VERSION 5.8 ;
BUSBITCHARS "[]" ;
DIVIDERCHAR "/" ;
UNITS
    DATABASE MICRONS 1000 ;
END UNITS

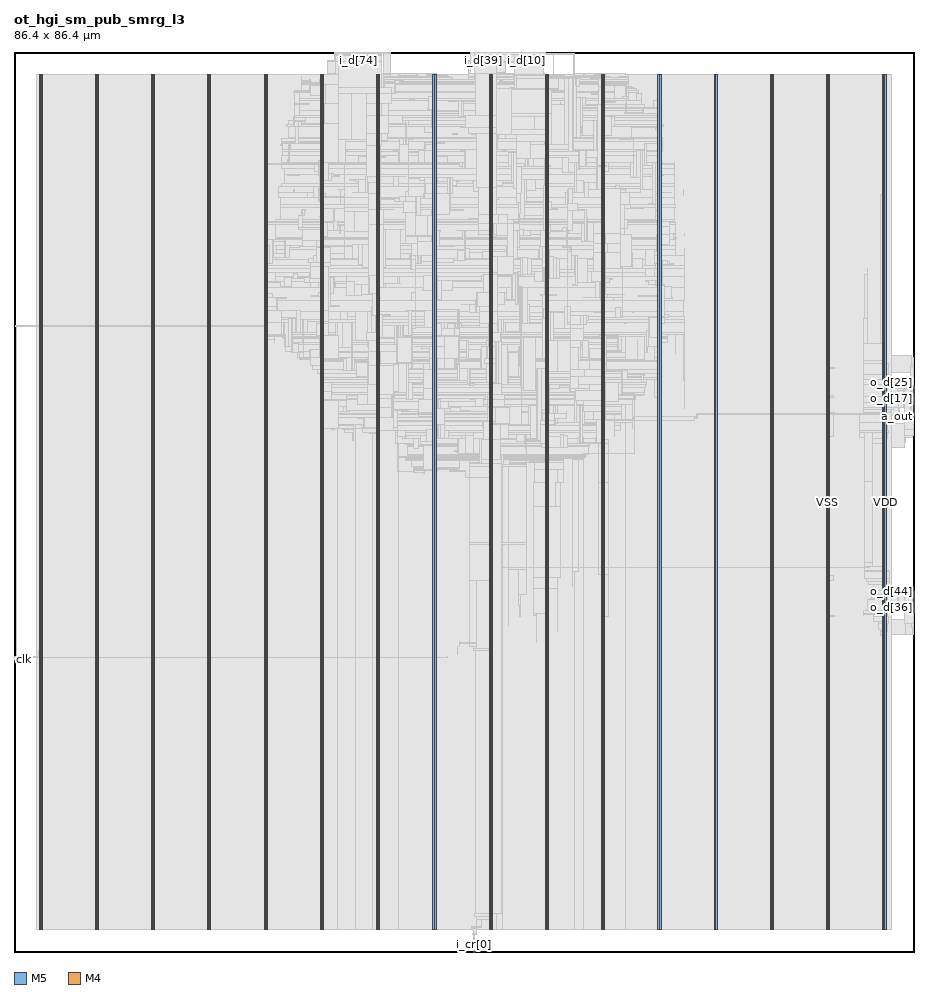
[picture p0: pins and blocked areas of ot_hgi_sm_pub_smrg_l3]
MACRO ot_hgi_sm_pub_smrg_l3
  FOREIGN ot_hgi_sm_pub_smrg_l3 0 0 ;
  CLASS BLOCK ;
  SIZE 86.4 BY 86.4 ;
  PIN a_in[0]
    DIRECTION INPUT ;
    USE SIGNAL ;
    PORT
      LAYER M5 ;
        RECT  48.048 86.316 48.072 86.4 ;
    END
  END a_in[0]
  PIN a_in[1]
    DIRECTION INPUT ;
    USE SIGNAL ;
    PORT
      LAYER M5 ;
        RECT  48.144 86.316 48.168 86.4 ;
    END
  END a_in[1]
  PIN a_out
    DIRECTION OUTPUT ;
    USE SIGNAL ;
    PORT
      LAYER M4 ;
        RECT  86.316 51.408 86.4 51.432 ;
    END
  END a_out
  PIN clk
    DIRECTION INPUT ;
    USE SIGNAL ;
    PORT
      LAYER M4 ;
        RECT  0 28.08 0.084 28.104 ;
    END
  END clk
  PIN i_cr[0]
    DIRECTION OUTPUT ;
    USE SIGNAL ;
    PORT
      LAYER M5 ;
        RECT  44.112 0 44.136 0.084 ;
    END
  END i_cr[0]
  PIN i_cr[1]
    DIRECTION OUTPUT ;
    USE SIGNAL ;
    PORT
      LAYER M5 ;
        RECT  44.208 0 44.232 0.084 ;
    END
  END i_cr[1]
  PIN i_d[0]
    DIRECTION INPUT ;
    USE SIGNAL ;
    PORT
      LAYER M5 ;
        RECT  48.24 86.316 48.264 86.4 ;
    END
  END i_d[0]
  PIN i_d[100]
    DIRECTION INPUT ;
    USE SIGNAL ;
    PORT
      LAYER M5 ;
        RECT  31.344 86.316 31.368 86.4 ;
    END
  END i_d[100]
  PIN i_d[101]
    DIRECTION INPUT ;
    USE SIGNAL ;
    PORT
      LAYER M5 ;
        RECT  31.44 86.316 31.464 86.4 ;
    END
  END i_d[101]
  PIN i_d[102]
    DIRECTION INPUT ;
    USE SIGNAL ;
    PORT
      LAYER M5 ;
        RECT  31.536 86.316 31.56 86.4 ;
    END
  END i_d[102]
  PIN i_d[103]
    DIRECTION INPUT ;
    USE SIGNAL ;
    PORT
      LAYER M5 ;
        RECT  31.632 86.316 31.656 86.4 ;
    END
  END i_d[103]
  PIN i_d[10]
    DIRECTION INPUT ;
    USE SIGNAL ;
    PORT
      LAYER M5 ;
        RECT  49.2 86.316 49.224 86.4 ;
    END
  END i_d[10]
  PIN i_d[11]
    DIRECTION INPUT ;
    USE SIGNAL ;
    PORT
      LAYER M5 ;
        RECT  49.296 86.316 49.32 86.4 ;
    END
  END i_d[11]
  PIN i_d[12]
    DIRECTION INPUT ;
    USE SIGNAL ;
    PORT
      LAYER M5 ;
        RECT  49.392 86.316 49.416 86.4 ;
    END
  END i_d[12]
  PIN i_d[13]
    DIRECTION INPUT ;
    USE SIGNAL ;
    PORT
      LAYER M5 ;
        RECT  49.488 86.316 49.512 86.4 ;
    END
  END i_d[13]
  PIN i_d[14]
    DIRECTION INPUT ;
    USE SIGNAL ;
    PORT
      LAYER M5 ;
        RECT  49.584 86.316 49.608 86.4 ;
    END
  END i_d[14]
  PIN i_d[15]
    DIRECTION INPUT ;
    USE SIGNAL ;
    PORT
      LAYER M5 ;
        RECT  49.68 86.316 49.704 86.4 ;
    END
  END i_d[15]
  PIN i_d[16]
    DIRECTION INPUT ;
    USE SIGNAL ;
    PORT
      LAYER M5 ;
        RECT  49.776 86.316 49.8 86.4 ;
    END
  END i_d[16]
  PIN i_d[17]
    DIRECTION INPUT ;
    USE SIGNAL ;
    PORT
      LAYER M5 ;
        RECT  49.872 86.316 49.896 86.4 ;
    END
  END i_d[17]
  PIN i_d[18]
    DIRECTION INPUT ;
    USE SIGNAL ;
    PORT
      LAYER M5 ;
        RECT  49.968 86.316 49.992 86.4 ;
    END
  END i_d[18]
  PIN i_d[19]
    DIRECTION INPUT ;
    USE SIGNAL ;
    PORT
      LAYER M5 ;
        RECT  50.064 86.316 50.088 86.4 ;
    END
  END i_d[19]
  PIN i_d[1]
    DIRECTION INPUT ;
    USE SIGNAL ;
    PORT
      LAYER M5 ;
        RECT  48.336 86.316 48.36 86.4 ;
    END
  END i_d[1]
  PIN i_d[20]
    DIRECTION INPUT ;
    USE SIGNAL ;
    PORT
      LAYER M5 ;
        RECT  50.16 86.316 50.184 86.4 ;
    END
  END i_d[20]
  PIN i_d[21]
    DIRECTION INPUT ;
    USE SIGNAL ;
    PORT
      LAYER M5 ;
        RECT  50.256 86.316 50.28 86.4 ;
    END
  END i_d[21]
  PIN i_d[22]
    DIRECTION INPUT ;
    USE SIGNAL ;
    PORT
      LAYER M5 ;
        RECT  50.352 86.316 50.376 86.4 ;
    END
  END i_d[22]
  PIN i_d[23]
    DIRECTION INPUT ;
    USE SIGNAL ;
    PORT
      LAYER M5 ;
        RECT  50.448 86.316 50.472 86.4 ;
    END
  END i_d[23]
  PIN i_d[24]
    DIRECTION INPUT ;
    USE SIGNAL ;
    PORT
      LAYER M5 ;
        RECT  50.544 86.316 50.568 86.4 ;
    END
  END i_d[24]
  PIN i_d[25]
    DIRECTION INPUT ;
    USE SIGNAL ;
    PORT
      LAYER M5 ;
        RECT  50.64 86.316 50.664 86.4 ;
    END
  END i_d[25]
  PIN i_d[26]
    DIRECTION INPUT ;
    USE SIGNAL ;
    PORT
      LAYER M5 ;
        RECT  50.736 86.316 50.76 86.4 ;
    END
  END i_d[26]
  PIN i_d[27]
    DIRECTION INPUT ;
    USE SIGNAL ;
    PORT
      LAYER M5 ;
        RECT  50.832 86.316 50.856 86.4 ;
    END
  END i_d[27]
  PIN i_d[28]
    DIRECTION INPUT ;
    USE SIGNAL ;
    PORT
      LAYER M5 ;
        RECT  50.928 86.316 50.952 86.4 ;
    END
  END i_d[28]
  PIN i_d[29]
    DIRECTION INPUT ;
    USE SIGNAL ;
    PORT
      LAYER M5 ;
        RECT  51.024 86.316 51.048 86.4 ;
    END
  END i_d[29]
  PIN i_d[2]
    DIRECTION INPUT ;
    USE SIGNAL ;
    PORT
      LAYER M5 ;
        RECT  48.432 86.316 48.456 86.4 ;
    END
  END i_d[2]
  PIN i_d[30]
    DIRECTION INPUT ;
    USE SIGNAL ;
    PORT
      LAYER M5 ;
        RECT  44.208 86.316 44.232 86.4 ;
    END
  END i_d[30]
  PIN i_d[31]
    DIRECTION INPUT ;
    USE SIGNAL ;
    PORT
      LAYER M5 ;
        RECT  44.304 86.316 44.328 86.4 ;
    END
  END i_d[31]
  PIN i_d[32]
    DIRECTION INPUT ;
    USE SIGNAL ;
    PORT
      LAYER M5 ;
        RECT  44.4 86.316 44.424 86.4 ;
    END
  END i_d[32]
  PIN i_d[33]
    DIRECTION INPUT ;
    USE SIGNAL ;
    PORT
      LAYER M5 ;
        RECT  44.496 86.316 44.52 86.4 ;
    END
  END i_d[33]
  PIN i_d[34]
    DIRECTION INPUT ;
    USE SIGNAL ;
    PORT
      LAYER M5 ;
        RECT  44.592 86.316 44.616 86.4 ;
    END
  END i_d[34]
  PIN i_d[35]
    DIRECTION INPUT ;
    USE SIGNAL ;
    PORT
      LAYER M5 ;
        RECT  44.688 86.316 44.712 86.4 ;
    END
  END i_d[35]
  PIN i_d[36]
    DIRECTION INPUT ;
    USE SIGNAL ;
    PORT
      LAYER M5 ;
        RECT  44.784 86.316 44.808 86.4 ;
    END
  END i_d[36]
  PIN i_d[37]
    DIRECTION INPUT ;
    USE SIGNAL ;
    PORT
      LAYER M5 ;
        RECT  44.88 86.316 44.904 86.4 ;
    END
  END i_d[37]
  PIN i_d[38]
    DIRECTION INPUT ;
    USE SIGNAL ;
    PORT
      LAYER M5 ;
        RECT  44.976 86.316 45 86.4 ;
    END
  END i_d[38]
  PIN i_d[39]
    DIRECTION INPUT ;
    USE SIGNAL ;
    PORT
      LAYER M5 ;
        RECT  45.072 86.316 45.096 86.4 ;
    END
  END i_d[39]
  PIN i_d[3]
    DIRECTION INPUT ;
    USE SIGNAL ;
    PORT
      LAYER M5 ;
        RECT  48.528 86.316 48.552 86.4 ;
    END
  END i_d[3]
  PIN i_d[40]
    DIRECTION INPUT ;
    USE SIGNAL ;
    PORT
      LAYER M5 ;
        RECT  45.168 86.316 45.192 86.4 ;
    END
  END i_d[40]
  PIN i_d[41]
    DIRECTION INPUT ;
    USE SIGNAL ;
    PORT
      LAYER M5 ;
        RECT  45.264 86.316 45.288 86.4 ;
    END
  END i_d[41]
  PIN i_d[42]
    DIRECTION INPUT ;
    USE SIGNAL ;
    PORT
      LAYER M5 ;
        RECT  45.36 86.316 45.384 86.4 ;
    END
  END i_d[42]
  PIN i_d[43]
    DIRECTION INPUT ;
    USE SIGNAL ;
    PORT
      LAYER M5 ;
        RECT  45.456 86.316 45.48 86.4 ;
    END
  END i_d[43]
  PIN i_d[44]
    DIRECTION INPUT ;
    USE SIGNAL ;
    PORT
      LAYER M5 ;
        RECT  45.552 86.316 45.576 86.4 ;
    END
  END i_d[44]
  PIN i_d[45]
    DIRECTION INPUT ;
    USE SIGNAL ;
    PORT
      LAYER M5 ;
        RECT  45.648 86.316 45.672 86.4 ;
    END
  END i_d[45]
  PIN i_d[46]
    DIRECTION INPUT ;
    USE SIGNAL ;
    PORT
      LAYER M5 ;
        RECT  45.744 86.316 45.768 86.4 ;
    END
  END i_d[46]
  PIN i_d[47]
    DIRECTION INPUT ;
    USE SIGNAL ;
    PORT
      LAYER M5 ;
        RECT  45.84 86.316 45.864 86.4 ;
    END
  END i_d[47]
  PIN i_d[48]
    DIRECTION INPUT ;
    USE SIGNAL ;
    PORT
      LAYER M5 ;
        RECT  45.936 86.316 45.96 86.4 ;
    END
  END i_d[48]
  PIN i_d[49]
    DIRECTION INPUT ;
    USE SIGNAL ;
    PORT
      LAYER M5 ;
        RECT  46.032 86.316 46.056 86.4 ;
    END
  END i_d[49]
  PIN i_d[4]
    DIRECTION INPUT ;
    USE SIGNAL ;
    PORT
      LAYER M5 ;
        RECT  48.624 86.316 48.648 86.4 ;
    END
  END i_d[4]
  PIN i_d[50]
    DIRECTION INPUT ;
    USE SIGNAL ;
    PORT
      LAYER M5 ;
        RECT  46.128 86.316 46.152 86.4 ;
    END
  END i_d[50]
  PIN i_d[51]
    DIRECTION INPUT ;
    USE SIGNAL ;
    PORT
      LAYER M5 ;
        RECT  46.224 86.316 46.248 86.4 ;
    END
  END i_d[51]
  PIN i_d[52]
    DIRECTION INPUT ;
    USE SIGNAL ;
    PORT
      LAYER M5 ;
        RECT  46.32 86.316 46.344 86.4 ;
    END
  END i_d[52]
  PIN i_d[53]
    DIRECTION INPUT ;
    USE SIGNAL ;
    PORT
      LAYER M5 ;
        RECT  46.416 86.316 46.44 86.4 ;
    END
  END i_d[53]
  PIN i_d[54]
    DIRECTION INPUT ;
    USE SIGNAL ;
    PORT
      LAYER M5 ;
        RECT  46.512 86.316 46.536 86.4 ;
    END
  END i_d[54]
  PIN i_d[55]
    DIRECTION INPUT ;
    USE SIGNAL ;
    PORT
      LAYER M5 ;
        RECT  46.608 86.316 46.632 86.4 ;
    END
  END i_d[55]
  PIN i_d[56]
    DIRECTION INPUT ;
    USE SIGNAL ;
    PORT
      LAYER M5 ;
        RECT  46.704 86.316 46.728 86.4 ;
    END
  END i_d[56]
  PIN i_d[57]
    DIRECTION INPUT ;
    USE SIGNAL ;
    PORT
      LAYER M5 ;
        RECT  46.8 86.316 46.824 86.4 ;
    END
  END i_d[57]
  PIN i_d[58]
    DIRECTION INPUT ;
    USE SIGNAL ;
    PORT
      LAYER M5 ;
        RECT  46.896 86.316 46.92 86.4 ;
    END
  END i_d[58]
  PIN i_d[59]
    DIRECTION INPUT ;
    USE SIGNAL ;
    PORT
      LAYER M5 ;
        RECT  46.992 86.316 47.016 86.4 ;
    END
  END i_d[59]
  PIN i_d[5]
    DIRECTION INPUT ;
    USE SIGNAL ;
    PORT
      LAYER M5 ;
        RECT  48.72 86.316 48.744 86.4 ;
    END
  END i_d[5]
  PIN i_d[60]
    DIRECTION INPUT ;
    USE SIGNAL ;
    PORT
      LAYER M5 ;
        RECT  47.088 86.316 47.112 86.4 ;
    END
  END i_d[60]
  PIN i_d[61]
    DIRECTION INPUT ;
    USE SIGNAL ;
    PORT
      LAYER M5 ;
        RECT  47.184 86.316 47.208 86.4 ;
    END
  END i_d[61]
  PIN i_d[62]
    DIRECTION INPUT ;
    USE SIGNAL ;
    PORT
      LAYER M5 ;
        RECT  31.92 86.316 31.944 86.4 ;
    END
  END i_d[62]
  PIN i_d[63]
    DIRECTION INPUT ;
    USE SIGNAL ;
    PORT
      LAYER M5 ;
        RECT  32.016 86.316 32.04 86.4 ;
    END
  END i_d[63]
  PIN i_d[64]
    DIRECTION INPUT ;
    USE SIGNAL ;
    PORT
      LAYER M5 ;
        RECT  32.112 86.316 32.136 86.4 ;
    END
  END i_d[64]
  PIN i_d[65]
    DIRECTION INPUT ;
    USE SIGNAL ;
    PORT
      LAYER M5 ;
        RECT  32.208 86.316 32.232 86.4 ;
    END
  END i_d[65]
  PIN i_d[66]
    DIRECTION INPUT ;
    USE SIGNAL ;
    PORT
      LAYER M5 ;
        RECT  32.304 86.316 32.328 86.4 ;
    END
  END i_d[66]
  PIN i_d[67]
    DIRECTION INPUT ;
    USE SIGNAL ;
    PORT
      LAYER M5 ;
        RECT  32.4 86.316 32.424 86.4 ;
    END
  END i_d[67]
  PIN i_d[68]
    DIRECTION INPUT ;
    USE SIGNAL ;
    PORT
      LAYER M5 ;
        RECT  32.496 86.316 32.52 86.4 ;
    END
  END i_d[68]
  PIN i_d[69]
    DIRECTION INPUT ;
    USE SIGNAL ;
    PORT
      LAYER M5 ;
        RECT  32.592 86.316 32.616 86.4 ;
    END
  END i_d[69]
  PIN i_d[6]
    DIRECTION INPUT ;
    USE SIGNAL ;
    PORT
      LAYER M5 ;
        RECT  48.816 86.316 48.84 86.4 ;
    END
  END i_d[6]
  PIN i_d[70]
    DIRECTION INPUT ;
    USE SIGNAL ;
    PORT
      LAYER M5 ;
        RECT  32.688 86.316 32.712 86.4 ;
    END
  END i_d[70]
  PIN i_d[71]
    DIRECTION INPUT ;
    USE SIGNAL ;
    PORT
      LAYER M5 ;
        RECT  32.784 86.316 32.808 86.4 ;
    END
  END i_d[71]
  PIN i_d[72]
    DIRECTION INPUT ;
    USE SIGNAL ;
    PORT
      LAYER M5 ;
        RECT  32.88 86.316 32.904 86.4 ;
    END
  END i_d[72]
  PIN i_d[73]
    DIRECTION INPUT ;
    USE SIGNAL ;
    PORT
      LAYER M5 ;
        RECT  32.976 86.316 33 86.4 ;
    END
  END i_d[73]
  PIN i_d[74]
    DIRECTION INPUT ;
    USE SIGNAL ;
    PORT
      LAYER M5 ;
        RECT  33.072 86.316 33.096 86.4 ;
    END
  END i_d[74]
  PIN i_d[75]
    DIRECTION INPUT ;
    USE SIGNAL ;
    PORT
      LAYER M5 ;
        RECT  33.168 86.316 33.192 86.4 ;
    END
  END i_d[75]
  PIN i_d[76]
    DIRECTION INPUT ;
    USE SIGNAL ;
    PORT
      LAYER M5 ;
        RECT  33.264 86.316 33.288 86.4 ;
    END
  END i_d[76]
  PIN i_d[77]
    DIRECTION INPUT ;
    USE SIGNAL ;
    PORT
      LAYER M5 ;
        RECT  33.36 86.316 33.384 86.4 ;
    END
  END i_d[77]
  PIN i_d[78]
    DIRECTION INPUT ;
    USE SIGNAL ;
    PORT
      LAYER M5 ;
        RECT  33.456 86.316 33.48 86.4 ;
    END
  END i_d[78]
  PIN i_d[79]
    DIRECTION INPUT ;
    USE SIGNAL ;
    PORT
      LAYER M5 ;
        RECT  33.552 86.316 33.576 86.4 ;
    END
  END i_d[79]
  PIN i_d[7]
    DIRECTION INPUT ;
    USE SIGNAL ;
    PORT
      LAYER M5 ;
        RECT  48.912 86.316 48.936 86.4 ;
    END
  END i_d[7]
  PIN i_d[80]
    DIRECTION INPUT ;
    USE SIGNAL ;
    PORT
      LAYER M5 ;
        RECT  33.648 86.316 33.672 86.4 ;
    END
  END i_d[80]
  PIN i_d[81]
    DIRECTION INPUT ;
    USE SIGNAL ;
    PORT
      LAYER M5 ;
        RECT  33.744 86.316 33.768 86.4 ;
    END
  END i_d[81]
  PIN i_d[82]
    DIRECTION INPUT ;
    USE SIGNAL ;
    PORT
      LAYER M5 ;
        RECT  33.84 86.316 33.864 86.4 ;
    END
  END i_d[82]
  PIN i_d[83]
    DIRECTION INPUT ;
    USE SIGNAL ;
    PORT
      LAYER M5 ;
        RECT  33.936 86.316 33.96 86.4 ;
    END
  END i_d[83]
  PIN i_d[84]
    DIRECTION INPUT ;
    USE SIGNAL ;
    PORT
      LAYER M5 ;
        RECT  34.032 86.316 34.056 86.4 ;
    END
  END i_d[84]
  PIN i_d[85]
    DIRECTION INPUT ;
    USE SIGNAL ;
    PORT
      LAYER M5 ;
        RECT  34.128 86.316 34.152 86.4 ;
    END
  END i_d[85]
  PIN i_d[86]
    DIRECTION INPUT ;
    USE SIGNAL ;
    PORT
      LAYER M5 ;
        RECT  34.224 86.316 34.248 86.4 ;
    END
  END i_d[86]
  PIN i_d[87]
    DIRECTION INPUT ;
    USE SIGNAL ;
    PORT
      LAYER M5 ;
        RECT  34.32 86.316 34.344 86.4 ;
    END
  END i_d[87]
  PIN i_d[88]
    DIRECTION INPUT ;
    USE SIGNAL ;
    PORT
      LAYER M5 ;
        RECT  34.416 86.316 34.44 86.4 ;
    END
  END i_d[88]
  PIN i_d[89]
    DIRECTION INPUT ;
    USE SIGNAL ;
    PORT
      LAYER M5 ;
        RECT  34.512 86.316 34.536 86.4 ;
    END
  END i_d[89]
  PIN i_d[8]
    DIRECTION INPUT ;
    USE SIGNAL ;
    PORT
      LAYER M5 ;
        RECT  49.008 86.316 49.032 86.4 ;
    END
  END i_d[8]
  PIN i_d[90]
    DIRECTION INPUT ;
    USE SIGNAL ;
    PORT
      LAYER M5 ;
        RECT  34.608 86.316 34.632 86.4 ;
    END
  END i_d[90]
  PIN i_d[91]
    DIRECTION INPUT ;
    USE SIGNAL ;
    PORT
      LAYER M5 ;
        RECT  34.704 86.316 34.728 86.4 ;
    END
  END i_d[91]
  PIN i_d[92]
    DIRECTION INPUT ;
    USE SIGNAL ;
    PORT
      LAYER M5 ;
        RECT  34.8 86.316 34.824 86.4 ;
    END
  END i_d[92]
  PIN i_d[93]
    DIRECTION INPUT ;
    USE SIGNAL ;
    PORT
      LAYER M5 ;
        RECT  34.896 86.316 34.92 86.4 ;
    END
  END i_d[93]
  PIN i_d[94]
    DIRECTION INPUT ;
    USE SIGNAL ;
    PORT
      LAYER M5 ;
        RECT  30.768 86.316 30.792 86.4 ;
    END
  END i_d[94]
  PIN i_d[95]
    DIRECTION INPUT ;
    USE SIGNAL ;
    PORT
      LAYER M5 ;
        RECT  30.864 86.316 30.888 86.4 ;
    END
  END i_d[95]
  PIN i_d[96]
    DIRECTION INPUT ;
    USE SIGNAL ;
    PORT
      LAYER M5 ;
        RECT  30.96 86.316 30.984 86.4 ;
    END
  END i_d[96]
  PIN i_d[97]
    DIRECTION INPUT ;
    USE SIGNAL ;
    PORT
      LAYER M5 ;
        RECT  31.056 86.316 31.08 86.4 ;
    END
  END i_d[97]
  PIN i_d[98]
    DIRECTION INPUT ;
    USE SIGNAL ;
    PORT
      LAYER M5 ;
        RECT  31.152 86.316 31.176 86.4 ;
    END
  END i_d[98]
  PIN i_d[99]
    DIRECTION INPUT ;
    USE SIGNAL ;
    PORT
      LAYER M5 ;
        RECT  31.248 86.316 31.272 86.4 ;
    END
  END i_d[99]
  PIN i_d[9]
    DIRECTION INPUT ;
    USE SIGNAL ;
    PORT
      LAYER M5 ;
        RECT  49.104 86.316 49.128 86.4 ;
    END
  END i_d[9]
  PIN i_v[0]
    DIRECTION INPUT ;
    USE SIGNAL ;
    PORT
      LAYER M5 ;
        RECT  31.728 86.316 31.752 86.4 ;
    END
  END i_v[0]
  PIN i_v[1]
    DIRECTION INPUT ;
    USE SIGNAL ;
    PORT
      LAYER M5 ;
        RECT  31.824 86.316 31.848 86.4 ;
    END
  END i_v[1]
  PIN o_cr
    DIRECTION INPUT ;
    USE SIGNAL ;
    PORT
      LAYER M4 ;
        RECT  0 28.176 0.084 28.2 ;
    END
  END o_cr
  PIN o_d[0]
    DIRECTION OUTPUT ;
    USE SIGNAL ;
    PORT
      LAYER M4 ;
        RECT  86.316 51.504 86.4 51.528 ;
    END
  END o_d[0]
  PIN o_d[10]
    DIRECTION OUTPUT ;
    USE SIGNAL ;
    PORT
      LAYER M4 ;
        RECT  86.316 52.464 86.4 52.488 ;
    END
  END o_d[10]
  PIN o_d[11]
    DIRECTION OUTPUT ;
    USE SIGNAL ;
    PORT
      LAYER M4 ;
        RECT  86.316 52.56 86.4 52.584 ;
    END
  END o_d[11]
  PIN o_d[12]
    DIRECTION OUTPUT ;
    USE SIGNAL ;
    PORT
      LAYER M4 ;
        RECT  86.316 52.656 86.4 52.68 ;
    END
  END o_d[12]
  PIN o_d[13]
    DIRECTION OUTPUT ;
    USE SIGNAL ;
    PORT
      LAYER M4 ;
        RECT  86.316 52.752 86.4 52.776 ;
    END
  END o_d[13]
  PIN o_d[14]
    DIRECTION OUTPUT ;
    USE SIGNAL ;
    PORT
      LAYER M4 ;
        RECT  86.316 52.848 86.4 52.872 ;
    END
  END o_d[14]
  PIN o_d[15]
    DIRECTION OUTPUT ;
    USE SIGNAL ;
    PORT
      LAYER M4 ;
        RECT  86.316 52.944 86.4 52.968 ;
    END
  END o_d[15]
  PIN o_d[16]
    DIRECTION OUTPUT ;
    USE SIGNAL ;
    PORT
      LAYER M4 ;
        RECT  86.316 53.04 86.4 53.064 ;
    END
  END o_d[16]
  PIN o_d[17]
    DIRECTION OUTPUT ;
    USE SIGNAL ;
    PORT
      LAYER M4 ;
        RECT  86.316 53.136 86.4 53.16 ;
    END
  END o_d[17]
  PIN o_d[18]
    DIRECTION OUTPUT ;
    USE SIGNAL ;
    PORT
      LAYER M4 ;
        RECT  86.316 53.232 86.4 53.256 ;
    END
  END o_d[18]
  PIN o_d[19]
    DIRECTION OUTPUT ;
    USE SIGNAL ;
    PORT
      LAYER M4 ;
        RECT  86.316 53.328 86.4 53.352 ;
    END
  END o_d[19]
  PIN o_d[1]
    DIRECTION OUTPUT ;
    USE SIGNAL ;
    PORT
      LAYER M4 ;
        RECT  86.316 51.6 86.4 51.624 ;
    END
  END o_d[1]
  PIN o_d[20]
    DIRECTION OUTPUT ;
    USE SIGNAL ;
    PORT
      LAYER M4 ;
        RECT  86.316 53.424 86.4 53.448 ;
    END
  END o_d[20]
  PIN o_d[21]
    DIRECTION OUTPUT ;
    USE SIGNAL ;
    PORT
      LAYER M4 ;
        RECT  86.316 53.52 86.4 53.544 ;
    END
  END o_d[21]
  PIN o_d[22]
    DIRECTION OUTPUT ;
    USE SIGNAL ;
    PORT
      LAYER M4 ;
        RECT  86.316 53.616 86.4 53.64 ;
    END
  END o_d[22]
  PIN o_d[23]
    DIRECTION OUTPUT ;
    USE SIGNAL ;
    PORT
      LAYER M4 ;
        RECT  86.316 53.712 86.4 53.736 ;
    END
  END o_d[23]
  PIN o_d[24]
    DIRECTION OUTPUT ;
    USE SIGNAL ;
    PORT
      LAYER M4 ;
        RECT  86.316 53.808 86.4 53.832 ;
    END
  END o_d[24]
  PIN o_d[25]
    DIRECTION OUTPUT ;
    USE SIGNAL ;
    PORT
      LAYER M4 ;
        RECT  86.316 53.904 86.4 53.928 ;
    END
  END o_d[25]
  PIN o_d[26]
    DIRECTION OUTPUT ;
    USE SIGNAL ;
    PORT
      LAYER M4 ;
        RECT  86.316 54 86.4 54.024 ;
    END
  END o_d[26]
  PIN o_d[27]
    DIRECTION OUTPUT ;
    USE SIGNAL ;
    PORT
      LAYER M4 ;
        RECT  86.316 54.096 86.4 54.12 ;
    END
  END o_d[27]
  PIN o_d[28]
    DIRECTION OUTPUT ;
    USE SIGNAL ;
    PORT
      LAYER M4 ;
        RECT  86.316 54.192 86.4 54.216 ;
    END
  END o_d[28]
  PIN o_d[29]
    DIRECTION OUTPUT ;
    USE SIGNAL ;
    PORT
      LAYER M4 ;
        RECT  86.316 54.288 86.4 54.312 ;
    END
  END o_d[29]
  PIN o_d[2]
    DIRECTION OUTPUT ;
    USE SIGNAL ;
    PORT
      LAYER M4 ;
        RECT  86.316 51.696 86.4 51.72 ;
    END
  END o_d[2]
  PIN o_d[30]
    DIRECTION OUTPUT ;
    USE SIGNAL ;
    PORT
      LAYER M4 ;
        RECT  86.316 54.384 86.4 54.408 ;
    END
  END o_d[30]
  PIN o_d[31]
    DIRECTION OUTPUT ;
    USE SIGNAL ;
    PORT
      LAYER M4 ;
        RECT  86.316 32.592 86.4 32.616 ;
    END
  END o_d[31]
  PIN o_d[32]
    DIRECTION OUTPUT ;
    USE SIGNAL ;
    PORT
      LAYER M4 ;
        RECT  86.316 32.688 86.4 32.712 ;
    END
  END o_d[32]
  PIN o_d[33]
    DIRECTION OUTPUT ;
    USE SIGNAL ;
    PORT
      LAYER M4 ;
        RECT  86.316 32.784 86.4 32.808 ;
    END
  END o_d[33]
  PIN o_d[34]
    DIRECTION OUTPUT ;
    USE SIGNAL ;
    PORT
      LAYER M4 ;
        RECT  86.316 32.88 86.4 32.904 ;
    END
  END o_d[34]
  PIN o_d[35]
    DIRECTION OUTPUT ;
    USE SIGNAL ;
    PORT
      LAYER M4 ;
        RECT  86.316 32.976 86.4 33 ;
    END
  END o_d[35]
  PIN o_d[36]
    DIRECTION OUTPUT ;
    USE SIGNAL ;
    PORT
      LAYER M4 ;
        RECT  86.316 33.072 86.4 33.096 ;
    END
  END o_d[36]
  PIN o_d[37]
    DIRECTION OUTPUT ;
    USE SIGNAL ;
    PORT
      LAYER M4 ;
        RECT  86.316 33.168 86.4 33.192 ;
    END
  END o_d[37]
  PIN o_d[38]
    DIRECTION OUTPUT ;
    USE SIGNAL ;
    PORT
      LAYER M4 ;
        RECT  86.316 33.264 86.4 33.288 ;
    END
  END o_d[38]
  PIN o_d[39]
    DIRECTION OUTPUT ;
    USE SIGNAL ;
    PORT
      LAYER M4 ;
        RECT  86.316 33.36 86.4 33.384 ;
    END
  END o_d[39]
  PIN o_d[3]
    DIRECTION OUTPUT ;
    USE SIGNAL ;
    PORT
      LAYER M4 ;
        RECT  86.316 51.792 86.4 51.816 ;
    END
  END o_d[3]
  PIN o_d[40]
    DIRECTION OUTPUT ;
    USE SIGNAL ;
    PORT
      LAYER M4 ;
        RECT  86.316 33.456 86.4 33.48 ;
    END
  END o_d[40]
  PIN o_d[41]
    DIRECTION OUTPUT ;
    USE SIGNAL ;
    PORT
      LAYER M4 ;
        RECT  86.316 33.552 86.4 33.576 ;
    END
  END o_d[41]
  PIN o_d[42]
    DIRECTION OUTPUT ;
    USE SIGNAL ;
    PORT
      LAYER M4 ;
        RECT  86.316 33.648 86.4 33.672 ;
    END
  END o_d[42]
  PIN o_d[43]
    DIRECTION OUTPUT ;
    USE SIGNAL ;
    PORT
      LAYER M4 ;
        RECT  86.316 33.744 86.4 33.768 ;
    END
  END o_d[43]
  PIN o_d[44]
    DIRECTION OUTPUT ;
    USE SIGNAL ;
    PORT
      LAYER M4 ;
        RECT  86.316 33.84 86.4 33.864 ;
    END
  END o_d[44]
  PIN o_d[45]
    DIRECTION OUTPUT ;
    USE SIGNAL ;
    PORT
      LAYER M4 ;
        RECT  86.316 33.936 86.4 33.96 ;
    END
  END o_d[45]
  PIN o_d[46]
    DIRECTION OUTPUT ;
    USE SIGNAL ;
    PORT
      LAYER M4 ;
        RECT  86.316 34.032 86.4 34.056 ;
    END
  END o_d[46]
  PIN o_d[47]
    DIRECTION OUTPUT ;
    USE SIGNAL ;
    PORT
      LAYER M4 ;
        RECT  86.316 34.128 86.4 34.152 ;
    END
  END o_d[47]
  PIN o_d[48]
    DIRECTION OUTPUT ;
    USE SIGNAL ;
    PORT
      LAYER M4 ;
        RECT  86.316 34.224 86.4 34.248 ;
    END
  END o_d[48]
  PIN o_d[49]
    DIRECTION OUTPUT ;
    USE SIGNAL ;
    PORT
      LAYER M4 ;
        RECT  86.316 34.32 86.4 34.344 ;
    END
  END o_d[49]
  PIN o_d[4]
    DIRECTION OUTPUT ;
    USE SIGNAL ;
    PORT
      LAYER M4 ;
        RECT  86.316 51.888 86.4 51.912 ;
    END
  END o_d[4]
  PIN o_d[50]
    DIRECTION OUTPUT ;
    USE SIGNAL ;
    PORT
      LAYER M4 ;
        RECT  86.316 34.416 86.4 34.44 ;
    END
  END o_d[50]
  PIN o_d[51]
    DIRECTION OUTPUT ;
    USE SIGNAL ;
    PORT
      LAYER M4 ;
        RECT  86.316 34.512 86.4 34.536 ;
    END
  END o_d[51]
  PIN o_d[5]
    DIRECTION OUTPUT ;
    USE SIGNAL ;
    PORT
      LAYER M4 ;
        RECT  86.316 51.984 86.4 52.008 ;
    END
  END o_d[5]
  PIN o_d[6]
    DIRECTION OUTPUT ;
    USE SIGNAL ;
    PORT
      LAYER M4 ;
        RECT  86.316 52.08 86.4 52.104 ;
    END
  END o_d[6]
  PIN o_d[7]
    DIRECTION OUTPUT ;
    USE SIGNAL ;
    PORT
      LAYER M4 ;
        RECT  86.316 52.176 86.4 52.2 ;
    END
  END o_d[7]
  PIN o_d[8]
    DIRECTION OUTPUT ;
    USE SIGNAL ;
    PORT
      LAYER M4 ;
        RECT  86.316 52.272 86.4 52.296 ;
    END
  END o_d[8]
  PIN o_d[9]
    DIRECTION OUTPUT ;
    USE SIGNAL ;
    PORT
      LAYER M4 ;
        RECT  86.316 52.368 86.4 52.392 ;
    END
  END o_d[9]
  PIN o_v
    DIRECTION OUTPUT ;
    USE SIGNAL ;
    PORT
      LAYER M4 ;
        RECT  86.316 34.608 86.4 34.632 ;
    END
  END o_v
  PIN rn
    DIRECTION INPUT ;
    USE SIGNAL ;
    PORT
      LAYER M4 ;
        RECT  0 28.272 0.084 28.296 ;
    END
  END rn
  PIN xb
    DIRECTION INPUT ;
    USE SIGNAL ;
    PORT
      LAYER M4 ;
        RECT  0 28.368 0.084 28.392 ;
    END
  END xb
  PIN VDD
    DIRECTION INOUT ;
    USE POWER ;
    PORT
      LAYER M5 ;
        RECT  83.592 2.151 83.712 84.249 ;
        RECT  78.192 2.151 78.312 84.249 ;
        RECT  72.792 2.151 72.912 84.249 ;
        RECT  67.392 2.151 67.512 84.249 ;
        RECT  61.992 2.151 62.112 84.249 ;
        RECT  56.592 2.151 56.712 84.249 ;
        RECT  51.192 2.151 51.312 84.249 ;
        RECT  45.792 2.151 45.912 84.249 ;
        RECT  40.392 2.151 40.512 84.249 ;
        RECT  34.992 2.151 35.112 84.249 ;
        RECT  29.592 2.151 29.712 84.249 ;
        RECT  24.192 2.151 24.312 84.249 ;
        RECT  18.792 2.151 18.912 84.249 ;
        RECT  13.392 2.151 13.512 84.249 ;
        RECT  7.992 2.151 8.112 84.249 ;
        RECT  2.592 2.151 2.712 84.249 ;
    END
  END VDD
  PIN VSS
    DIRECTION INOUT ;
    USE GROUND ;
    PORT
      LAYER M5 ;
        RECT  83.4 2.137 83.52 84.263 ;
        RECT  78 2.137 78.12 84.263 ;
        RECT  72.6 2.137 72.72 84.263 ;
        RECT  67.2 2.137 67.32 84.263 ;
        RECT  61.8 2.137 61.92 84.263 ;
        RECT  56.4 2.137 56.52 84.263 ;
        RECT  51 2.137 51.12 84.263 ;
        RECT  45.6 2.137 45.72 84.263 ;
        RECT  40.2 2.137 40.32 84.263 ;
        RECT  34.8 2.137 34.92 84.263 ;
        RECT  29.4 2.137 29.52 84.263 ;
        RECT  24 2.137 24.12 84.263 ;
        RECT  18.6 2.137 18.72 84.263 ;
        RECT  13.2 2.137 13.32 84.263 ;
        RECT  7.8 2.137 7.92 84.263 ;
        RECT  2.4 2.137 2.52 84.263 ;
    END
  END VSS
  # OT_OBS_CLOSED layer=M5 d_um=1.536 added=95
  OBS
    LAYER RVTN ;
     RECT  2.16 2.16 84.24 2.295 ;
     RECT  2.16 2.565 84.24 2.835 ;
     RECT  2.16 3.105 84.24 3.375 ;
     RECT  2.16 3.645 84.24 3.915 ;
     RECT  2.16 4.185 84.24 4.455 ;
     RECT  2.16 4.725 84.24 4.995 ;
     RECT  2.16 5.265 84.24 5.535 ;
     RECT  2.16 5.805 84.24 6.075 ;
     RECT  2.16 6.345 84.24 6.615 ;
     RECT  2.16 6.885 84.24 7.155 ;
     RECT  2.16 7.425 84.24 7.695 ;
     RECT  2.16 7.965 84.24 8.235 ;
     RECT  2.16 8.505 84.24 8.775 ;
     RECT  2.16 9.045 84.24 9.315 ;
     RECT  2.16 9.585 84.24 9.855 ;
     RECT  2.16 10.125 84.24 10.395 ;
     RECT  2.16 10.665 84.24 10.935 ;
     RECT  2.16 11.205 84.24 11.475 ;
     RECT  2.16 11.745 84.24 12.015 ;
     RECT  2.16 12.285 84.24 12.555 ;
     RECT  2.16 12.825 84.24 13.095 ;
     RECT  2.16 13.365 84.24 13.635 ;
     RECT  2.16 13.905 84.24 14.175 ;
     RECT  2.16 14.445 84.24 14.715 ;
     RECT  2.16 14.985 84.24 15.255 ;
     RECT  2.16 15.525 84.24 15.795 ;
     RECT  2.16 16.065 84.24 16.335 ;
     RECT  2.16 16.605 84.24 16.875 ;
     RECT  2.16 17.145 84.24 17.415 ;
     RECT  2.16 17.685 84.24 17.955 ;
     RECT  2.16 18.225 84.24 18.495 ;
     RECT  2.16 18.765 84.24 19.035 ;
     RECT  2.16 19.305 84.24 19.575 ;
     RECT  2.16 19.845 84.24 20.115 ;
     RECT  2.16 20.385 84.24 20.655 ;
     RECT  2.16 20.925 84.24 21.195 ;
     RECT  2.16 21.465 84.24 21.735 ;
     RECT  2.16 22.005 84.24 22.275 ;
     RECT  2.16 22.545 84.24 22.815 ;
     RECT  2.16 23.085 84.24 23.355 ;
     RECT  2.16 23.625 84.24 23.895 ;
     RECT  2.16 24.165 84.24 24.435 ;
     RECT  2.16 24.705 84.24 24.975 ;
     RECT  2.16 25.245 84.24 25.515 ;
     RECT  2.16 25.785 84.24 26.055 ;
     RECT  2.16 26.325 84.24 26.595 ;
     RECT  2.16 26.865 84.24 27.135 ;
     RECT  2.16 27.405 84.24 27.675 ;
     RECT  2.16 27.945 84.24 28.215 ;
     RECT  2.16 28.485 84.24 28.755 ;
     RECT  2.16 29.025 84.24 29.295 ;
     RECT  2.16 29.565 84.24 29.835 ;
     RECT  2.16 30.105 84.24 30.375 ;
     RECT  2.16 30.645 84.24 30.915 ;
     RECT  2.16 31.185 84.24 31.455 ;
     RECT  2.16 31.725 84.24 31.995 ;
     RECT  2.16 32.265 84.24 32.535 ;
     RECT  2.16 32.805 84.24 33.075 ;
     RECT  2.16 33.345 84.24 33.615 ;
     RECT  2.16 33.885 84.24 34.155 ;
     RECT  2.16 34.425 84.24 34.695 ;
     RECT  2.16 34.965 84.24 35.235 ;
     RECT  2.16 35.505 84.24 35.775 ;
     RECT  2.16 36.045 84.24 36.315 ;
     RECT  2.16 36.585 84.24 36.855 ;
     RECT  2.16 37.125 84.24 37.395 ;
     RECT  2.16 37.665 84.24 37.935 ;
     RECT  2.16 38.205 84.24 38.475 ;
     RECT  2.16 38.745 84.24 39.015 ;
     RECT  2.16 39.285 84.24 39.555 ;
     RECT  2.16 39.825 84.24 40.095 ;
     RECT  2.16 40.365 84.24 40.635 ;
     RECT  2.16 40.905 84.24 41.175 ;
     RECT  2.16 41.445 84.24 41.715 ;
     RECT  2.16 41.985 84.24 42.255 ;
     RECT  2.16 42.525 84.24 42.795 ;
     RECT  2.16 43.065 84.24 43.335 ;
     RECT  2.16 43.605 84.24 43.875 ;
     RECT  2.16 44.145 84.24 44.415 ;
     RECT  2.16 44.685 84.24 44.955 ;
     RECT  2.16 45.225 84.24 45.495 ;
     RECT  2.16 45.765 84.24 46.035 ;
     RECT  2.16 46.305 84.24 46.575 ;
     RECT  2.16 46.845 84.24 47.115 ;
     RECT  2.16 47.385 84.24 47.655 ;
     RECT  2.16 47.925 84.24 48.195 ;
     RECT  2.16 48.465 84.24 48.735 ;
     RECT  2.16 49.005 84.24 49.275 ;
     RECT  2.16 49.545 84.24 49.815 ;
     RECT  2.16 50.085 84.24 50.355 ;
     RECT  2.16 50.625 84.24 50.895 ;
     RECT  2.16 51.165 84.24 51.435 ;
     RECT  2.16 51.705 84.24 51.975 ;
     RECT  2.16 52.245 84.24 52.515 ;
     RECT  2.16 52.785 84.24 53.055 ;
     RECT  2.16 53.325 84.24 53.595 ;
     RECT  2.16 53.865 84.24 54.135 ;
     RECT  2.16 54.405 84.24 54.675 ;
     RECT  2.16 54.945 84.24 55.215 ;
     RECT  2.16 55.485 84.24 55.755 ;
     RECT  2.16 56.025 84.24 56.295 ;
     RECT  2.16 56.565 84.24 56.835 ;
     RECT  2.16 57.105 84.24 57.375 ;
     RECT  2.16 57.645 84.24 57.915 ;
     RECT  2.16 58.185 84.24 58.455 ;
     RECT  2.16 58.725 84.24 58.995 ;
     RECT  2.16 59.265 84.24 59.535 ;
     RECT  2.16 59.805 84.24 60.075 ;
     RECT  2.16 60.345 84.24 60.615 ;
     RECT  2.16 60.885 84.24 61.155 ;
     RECT  2.16 61.425 84.24 61.695 ;
     RECT  2.16 61.965 84.24 62.235 ;
     RECT  2.16 62.505 84.24 62.775 ;
     RECT  2.16 63.045 84.24 63.315 ;
     RECT  2.16 63.585 84.24 63.855 ;
     RECT  2.16 64.125 84.24 64.395 ;
     RECT  2.16 64.665 84.24 64.935 ;
     RECT  2.16 65.205 84.24 65.475 ;
     RECT  2.16 65.745 84.24 66.015 ;
     RECT  2.16 66.285 84.24 66.555 ;
     RECT  2.16 66.825 84.24 67.095 ;
     RECT  2.16 67.365 84.24 67.635 ;
     RECT  2.16 67.905 84.24 68.175 ;
     RECT  2.16 68.445 84.24 68.715 ;
     RECT  2.16 68.985 84.24 69.255 ;
     RECT  2.16 69.525 84.24 69.795 ;
     RECT  2.16 70.065 84.24 70.335 ;
     RECT  2.16 70.605 84.24 70.875 ;
     RECT  2.16 71.145 84.24 71.415 ;
     RECT  2.16 71.685 84.24 71.955 ;
     RECT  2.16 72.225 84.24 72.495 ;
     RECT  2.16 72.765 84.24 73.035 ;
     RECT  2.16 73.305 84.24 73.575 ;
     RECT  2.16 73.845 84.24 74.115 ;
     RECT  2.16 74.385 84.24 74.655 ;
     RECT  2.16 74.925 84.24 75.195 ;
     RECT  2.16 75.465 84.24 75.735 ;
     RECT  2.16 76.005 84.24 76.275 ;
     RECT  2.16 76.545 84.24 76.815 ;
     RECT  2.16 77.085 84.24 77.355 ;
     RECT  2.16 77.625 84.24 77.895 ;
     RECT  2.16 78.165 84.24 78.435 ;
     RECT  2.16 78.705 84.24 78.975 ;
     RECT  2.16 79.245 84.24 79.515 ;
     RECT  2.16 79.785 84.24 80.055 ;
     RECT  2.16 80.325 84.24 80.595 ;
     RECT  2.16 80.865 84.24 81.135 ;
     RECT  2.16 81.405 84.24 81.675 ;
     RECT  2.16 81.945 84.24 82.215 ;
     RECT  2.16 82.485 84.24 82.755 ;
     RECT  2.16 83.025 84.24 83.295 ;
     RECT  2.16 83.565 84.24 83.835 ;
     RECT  2.16 84.105 84.24 84.24 ;
    LAYER RVTP ;
     RECT  2.16 2.295 84.24 2.565 ;
     RECT  2.16 2.835 84.24 3.105 ;
     RECT  2.16 3.375 84.24 3.645 ;
     RECT  2.16 3.915 84.24 4.185 ;
     RECT  2.16 4.455 84.24 4.725 ;
     RECT  2.16 4.995 84.24 5.265 ;
     RECT  2.16 5.535 84.24 5.805 ;
     RECT  2.16 6.075 84.24 6.345 ;
     RECT  2.16 6.615 84.24 6.885 ;
     RECT  2.16 7.155 84.24 7.425 ;
     RECT  2.16 7.695 84.24 7.965 ;
     RECT  2.16 8.235 84.24 8.505 ;
     RECT  2.16 8.775 84.24 9.045 ;
     RECT  2.16 9.315 84.24 9.585 ;
     RECT  2.16 9.855 84.24 10.125 ;
     RECT  2.16 10.395 84.24 10.665 ;
     RECT  2.16 10.935 84.24 11.205 ;
     RECT  2.16 11.475 84.24 11.745 ;
     RECT  2.16 12.015 84.24 12.285 ;
     RECT  2.16 12.555 84.24 12.825 ;
     RECT  2.16 13.095 84.24 13.365 ;
     RECT  2.16 13.635 84.24 13.905 ;
     RECT  2.16 14.175 84.24 14.445 ;
     RECT  2.16 14.715 84.24 14.985 ;
     RECT  2.16 15.255 84.24 15.525 ;
     RECT  2.16 15.795 84.24 16.065 ;
     RECT  2.16 16.335 84.24 16.605 ;
     RECT  2.16 16.875 84.24 17.145 ;
     RECT  2.16 17.415 84.24 17.685 ;
     RECT  2.16 17.955 84.24 18.225 ;
     RECT  2.16 18.495 84.24 18.765 ;
     RECT  2.16 19.035 84.24 19.305 ;
     RECT  2.16 19.575 84.24 19.845 ;
     RECT  2.16 20.115 84.24 20.385 ;
     RECT  2.16 20.655 84.24 20.925 ;
     RECT  2.16 21.195 84.24 21.465 ;
     RECT  2.16 21.735 84.24 22.005 ;
     RECT  2.16 22.275 84.24 22.545 ;
     RECT  2.16 22.815 84.24 23.085 ;
     RECT  2.16 23.355 84.24 23.625 ;
     RECT  2.16 23.895 84.24 24.165 ;
     RECT  2.16 24.435 84.24 24.705 ;
     RECT  2.16 24.975 84.24 25.245 ;
     RECT  2.16 25.515 84.24 25.785 ;
     RECT  2.16 26.055 84.24 26.325 ;
     RECT  2.16 26.595 84.24 26.865 ;
     RECT  2.16 27.135 84.24 27.405 ;
     RECT  2.16 27.675 84.24 27.945 ;
     RECT  2.16 28.215 84.24 28.485 ;
     RECT  2.16 28.755 84.24 29.025 ;
     RECT  2.16 29.295 84.24 29.565 ;
     RECT  2.16 29.835 84.24 30.105 ;
     RECT  2.16 30.375 84.24 30.645 ;
     RECT  2.16 30.915 84.24 31.185 ;
     RECT  2.16 31.455 84.24 31.725 ;
     RECT  2.16 31.995 84.24 32.265 ;
     RECT  2.16 32.535 84.24 32.805 ;
     RECT  2.16 33.075 84.24 33.345 ;
     RECT  2.16 33.615 84.24 33.885 ;
     RECT  2.16 34.155 84.24 34.425 ;
     RECT  2.16 34.695 84.24 34.965 ;
     RECT  2.16 35.235 84.24 35.505 ;
     RECT  2.16 35.775 84.24 36.045 ;
     RECT  2.16 36.315 84.24 36.585 ;
     RECT  2.16 36.855 84.24 37.125 ;
     RECT  2.16 37.395 84.24 37.665 ;
     RECT  2.16 37.935 84.24 38.205 ;
     RECT  2.16 38.475 84.24 38.745 ;
     RECT  2.16 39.015 84.24 39.285 ;
     RECT  2.16 39.555 84.24 39.825 ;
     RECT  2.16 40.095 84.24 40.365 ;
     RECT  2.16 40.635 84.24 40.905 ;
     RECT  2.16 41.175 84.24 41.445 ;
     RECT  2.16 41.715 84.24 41.985 ;
     RECT  2.16 42.255 84.24 42.525 ;
     RECT  2.16 42.795 84.24 43.065 ;
     RECT  2.16 43.335 84.24 43.605 ;
     RECT  2.16 43.875 84.24 44.145 ;
     RECT  2.16 44.415 84.24 44.685 ;
     RECT  2.16 44.955 84.24 45.225 ;
     RECT  2.16 45.495 84.24 45.765 ;
     RECT  2.16 46.035 84.24 46.305 ;
     RECT  2.16 46.575 84.24 46.845 ;
     RECT  2.16 47.115 84.24 47.385 ;
     RECT  2.16 47.655 84.24 47.925 ;
     RECT  2.16 48.195 84.24 48.465 ;
     RECT  2.16 48.735 84.24 49.005 ;
     RECT  2.16 49.275 84.24 49.545 ;
     RECT  2.16 49.815 84.24 50.085 ;
     RECT  2.16 50.355 84.24 50.625 ;
     RECT  2.16 50.895 84.24 51.165 ;
     RECT  2.16 51.435 84.24 51.705 ;
     RECT  2.16 51.975 84.24 52.245 ;
     RECT  2.16 52.515 84.24 52.785 ;
     RECT  2.16 53.055 84.24 53.325 ;
     RECT  2.16 53.595 84.24 53.865 ;
     RECT  2.16 54.135 84.24 54.405 ;
     RECT  2.16 54.675 84.24 54.945 ;
     RECT  2.16 55.215 84.24 55.485 ;
     RECT  2.16 55.755 84.24 56.025 ;
     RECT  2.16 56.295 84.24 56.565 ;
     RECT  2.16 56.835 84.24 57.105 ;
     RECT  2.16 57.375 84.24 57.645 ;
     RECT  2.16 57.915 84.24 58.185 ;
     RECT  2.16 58.455 84.24 58.725 ;
     RECT  2.16 58.995 84.24 59.265 ;
     RECT  2.16 59.535 84.24 59.805 ;
     RECT  2.16 60.075 84.24 60.345 ;
     RECT  2.16 60.615 84.24 60.885 ;
     RECT  2.16 61.155 84.24 61.425 ;
     RECT  2.16 61.695 84.24 61.965 ;
     RECT  2.16 62.235 84.24 62.505 ;
     RECT  2.16 62.775 84.24 63.045 ;
     RECT  2.16 63.315 84.24 63.585 ;
     RECT  2.16 63.855 84.24 64.125 ;
     RECT  2.16 64.395 84.24 64.665 ;
     RECT  2.16 64.935 84.24 65.205 ;
     RECT  2.16 65.475 84.24 65.745 ;
     RECT  2.16 66.015 84.24 66.285 ;
     RECT  2.16 66.555 84.24 66.825 ;
     RECT  2.16 67.095 84.24 67.365 ;
     RECT  2.16 67.635 84.24 67.905 ;
     RECT  2.16 68.175 84.24 68.445 ;
     RECT  2.16 68.715 84.24 68.985 ;
     RECT  2.16 69.255 84.24 69.525 ;
     RECT  2.16 69.795 84.24 70.065 ;
     RECT  2.16 70.335 84.24 70.605 ;
     RECT  2.16 70.875 84.24 71.145 ;
     RECT  2.16 71.415 84.24 71.685 ;
     RECT  2.16 71.955 84.24 72.225 ;
     RECT  2.16 72.495 84.24 72.765 ;
     RECT  2.16 73.035 84.24 73.305 ;
     RECT  2.16 73.575 84.24 73.845 ;
     RECT  2.16 74.115 84.24 74.385 ;
     RECT  2.16 74.655 84.24 74.925 ;
     RECT  2.16 75.195 84.24 75.465 ;
     RECT  2.16 75.735 84.24 76.005 ;
     RECT  2.16 76.275 84.24 76.545 ;
     RECT  2.16 76.815 84.24 77.085 ;
     RECT  2.16 77.355 84.24 77.625 ;
     RECT  2.16 77.895 84.24 78.165 ;
     RECT  2.16 78.435 84.24 78.705 ;
     RECT  2.16 78.975 84.24 79.245 ;
     RECT  2.16 79.515 84.24 79.785 ;
     RECT  2.16 80.055 84.24 80.325 ;
     RECT  2.16 80.595 84.24 80.865 ;
     RECT  2.16 81.135 84.24 81.405 ;
     RECT  2.16 81.675 84.24 81.945 ;
     RECT  2.16 82.215 84.24 82.485 ;
     RECT  2.16 82.755 84.24 83.025 ;
     RECT  2.16 83.295 84.24 83.565 ;
     RECT  2.16 83.835 84.24 84.105 ;
    LAYER M1 ;
     RECT  2.16 2.151 84.24 84.249 ;
    LAYER M2 ;
     RECT  2.16 2.151 31.027 84.249 ;
     RECT  31.027 2.151 32.783 84.294 ;
     RECT  32.783 2.151 34.411 84.249 ;
     RECT  34.411 2.151 36.895 84.294 ;
     RECT  36.895 2.151 40.595 84.366 ;
     RECT  40.595 2.151 46.291 84.249 ;
     RECT  46.291 2.151 46.895 84.906 ;
     RECT  46.895 2.151 53.779 84.249 ;
     RECT  53.779 2.151 54.715 84.294 ;
     RECT  54.715 2.151 58.703 84.366 ;
     RECT  58.703 2.151 84.24 84.249 ;
     RECT  84.24 32.85 84.839 34.758 ;
     RECT  84.839 32.85 84.875 34.722 ;
     RECT  84.24 51.516 84.875 54.666 ;
     RECT  84.875 32.85 84.947 34.614 ;
     RECT  84.947 32.886 84.983 34.614 ;
     RECT  84.875 51.516 84.983 54.594 ;
     RECT  84.983 52.686 85.415 54.594 ;
     RECT  85.415 52.686 85.451 54.324 ;
     RECT  84.983 33.048 85.487 34.614 ;
     RECT  85.451 52.686 85.487 54.054 ;
     RECT  84.24 48.438 85.523 50.724 ;
     RECT  84.983 51.516 85.523 51.534 ;
     RECT  85.487 53.406 85.523 54.054 ;
     RECT  84.24 30.456 85.595 31.914 ;
     RECT  85.523 48.906 85.595 50.724 ;
     RECT  85.595 49.356 86.135 50.724 ;
     RECT  84.24 55.656 86.171 57.294 ;
     RECT  86.135 49.356 86.207 50.454 ;
     RECT  86.171 57.006 86.207 57.294 ;
     RECT  85.595 30.456 86.243 31.824 ;
     RECT  86.243 30.456 86.279 31.284 ;
     RECT  85.487 33.048 86.279 33.606 ;
     RECT  86.207 49.356 86.279 50.148 ;
     RECT  86.171 55.656 86.279 56.124 ;
     RECT  86.279 33.048 86.287 33.066 ;
     RECT  86.279 30.456 86.315 31.014 ;
     RECT  86.287 32.976 86.315 33.066 ;
     RECT  86.279 49.554 86.315 50.148 ;
     RECT  86.279 55.656 86.315 55.674 ;
     RECT  86.315 50.13 86.351 50.148 ;
     RECT  86.251 51.786 86.351 51.804 ;
     RECT  86.315 30.456 86.387 30.474 ;
     RECT  86.315 32.976 86.387 32.994 ;
     RECT  86.179 54.108 86.387 54.126 ;
     RECT  86.207 57.006 86.387 57.024 ;
    LAYER M3 ;
     RECT  44.064 1.723 44.406 2.227 ;
     RECT  43.884 2.227 44.406 2.371 ;
     RECT  2.415 2.143 2.505 2.413 ;
     RECT  7.815 2.143 7.905 2.413 ;
     RECT  13.215 2.143 13.305 2.413 ;
     RECT  18.615 2.143 18.705 2.413 ;
     RECT  24.015 2.143 24.105 2.413 ;
     RECT  29.415 2.143 29.505 2.413 ;
     RECT  34.815 2.143 34.905 2.413 ;
     RECT  40.215 2.143 40.305 2.413 ;
     RECT  45.615 2.143 45.705 2.413 ;
     RECT  51.015 2.143 51.105 2.413 ;
     RECT  56.415 2.143 56.505 2.413 ;
     RECT  61.815 2.143 61.905 2.413 ;
     RECT  67.215 2.143 67.305 2.413 ;
     RECT  72.615 2.143 72.705 2.413 ;
     RECT  78.015 2.143 78.105 2.413 ;
     RECT  83.415 2.143 83.505 2.413 ;
     RECT  43.884 2.371 44.874 2.489 ;
     RECT  44.388 2.489 44.874 3.145 ;
     RECT  45.615 2.413 45.897 3.145 ;
     RECT  44.388 3.145 45.897 3.379 ;
     RECT  44.352 3.379 45.897 3.415 ;
     RECT  44.244 3.415 45.897 3.725 ;
     RECT  2.415 2.413 2.697 28.363 ;
     RECT  41.616 28.267 41.634 28.409 ;
     RECT  44.352 3.725 45.897 28.921 ;
     RECT  2.304 28.363 2.697 28.985 ;
     RECT  44.1 28.921 45.897 29.093 ;
     RECT  44.1 29.093 44.442 29.335 ;
     RECT  42.588 28.561 42.606 29.363 ;
     RECT  42.732 29.371 42.75 29.605 ;
     RECT  43.704 29.335 44.442 29.605 ;
     RECT  42.732 29.605 44.442 29.759 ;
     RECT  42.732 29.759 42.75 29.795 ;
     RECT  83.415 2.413 83.697 30.415 ;
     RECT  83.16 30.415 83.697 30.721 ;
     RECT  83.16 30.721 83.898 30.991 ;
     RECT  86.364 30.451 86.382 30.991 ;
     RECT  86.292 30.991 86.382 31.189 ;
     RECT  82.98 30.991 83.898 31.531 ;
     RECT  86.184 31.189 86.382 31.531 ;
     RECT  82.98 31.531 83.97 31.721 ;
     RECT  82.98 31.721 83.934 31.765 ;
     RECT  82.548 31.765 83.934 32.189 ;
     RECT  56.415 2.413 56.697 32.197 ;
     RECT  78.015 2.413 78.297 32.197 ;
     RECT  78.015 32.197 78.75 32.297 ;
     RECT  50.148 29.731 50.166 32.341 ;
     RECT  81.504 32.341 81.522 32.431 ;
     RECT  82.548 32.189 83.898 32.431 ;
     RECT  81.504 32.431 83.898 32.459 ;
     RECT  49.896 32.341 50.166 32.467 ;
     RECT  51.015 2.413 51.297 32.467 ;
     RECT  81.54 32.459 83.898 32.801 ;
     RECT  85.5 31.531 86.382 32.845 ;
     RECT  84.924 32.845 86.382 32.999 ;
     RECT  48.564 32.161 48.582 33.241 ;
     RECT  84.924 32.999 86.31 33.293 ;
     RECT  86.256 33.293 86.31 33.677 ;
     RECT  45.615 29.093 45.897 33.781 ;
     RECT  46.656 31.891 46.674 33.781 ;
     RECT  81.972 32.801 83.898 33.845 ;
     RECT  84.924 33.293 85.518 33.869 ;
     RECT  82.116 33.845 83.898 33.917 ;
     RECT  86.256 33.677 86.274 33.965 ;
     RECT  84.924 33.869 85.482 34.027 ;
     RECT  82.368 33.917 83.898 34.123 ;
     RECT  84.888 34.027 85.482 34.219 ;
     RECT  48.384 33.241 48.582 34.321 ;
     RECT  82.368 34.123 83.97 34.349 ;
     RECT  84.852 34.219 85.482 34.603 ;
     RECT  84.816 34.603 85.482 34.619 ;
     RECT  82.548 34.349 83.97 34.663 ;
     RECT  84.816 34.619 84.87 34.727 ;
     RECT  84.816 34.727 84.834 34.763 ;
     RECT  49.896 32.467 51.297 34.897 ;
     RECT  52.128 30.811 52.146 34.897 ;
     RECT  82.548 34.663 84.006 35.275 ;
     RECT  82.08 35.275 84.006 35.545 ;
     RECT  43.704 29.759 44.442 35.707 ;
     RECT  45.615 33.781 46.674 35.707 ;
     RECT  78.015 32.297 78.297 35.707 ;
     RECT  81.864 35.545 84.006 35.851 ;
     RECT  49.896 34.897 52.146 35.977 ;
     RECT  78.015 35.707 78.678 36.149 ;
     RECT  56.415 32.197 57.042 36.211 ;
     RECT  53.568 35.131 53.586 36.481 ;
     RECT  81.612 35.851 84.006 36.509 ;
     RECT  81.612 36.509 83.934 36.581 ;
     RECT  47.484 31.351 47.502 36.751 ;
     RECT  48.384 34.321 49.158 36.751 ;
     RECT  81.612 36.581 83.697 37.049 ;
     RECT  83.376 37.049 83.697 37.319 ;
     RECT  81.612 37.049 82.458 37.355 ;
     RECT  43.704 35.707 46.674 39.091 ;
     RECT  47.484 36.751 49.158 39.091 ;
     RECT  43.704 39.091 49.158 39.341 ;
     RECT  49.896 35.977 52.506 42.791 ;
     RECT  52.02 42.791 52.506 45.031 ;
     RECT  49.896 42.791 51.297 45.059 ;
     RECT  52.02 45.031 52.722 45.059 ;
     RECT  56.088 36.211 57.042 45.059 ;
     RECT  81.612 37.355 82.422 45.149 ;
     RECT  43.704 39.341 46.674 45.535 ;
     RECT  43.668 45.535 46.674 45.581 ;
     RECT  39.348 45.931 39.366 46.039 ;
     RECT  38.772 46.039 39.366 46.075 ;
     RECT  40.215 2.413 40.497 46.237 ;
     RECT  38.376 46.075 39.366 46.267 ;
     RECT  40.104 46.237 40.497 46.267 ;
     RECT  38.376 46.267 40.626 46.273 ;
     RECT  41.796 46.171 41.814 46.273 ;
     RECT  42.66 46.111 42.678 46.273 ;
     RECT  49.968 45.059 51.297 46.309 ;
     RECT  52.2 45.059 52.722 46.309 ;
     RECT  38.376 46.273 42.678 46.381 ;
     RECT  38.376 46.381 42.75 46.535 ;
     RECT  43.704 45.581 46.674 46.579 ;
     RECT  38.376 46.535 39.402 46.615 ;
     RECT  43.704 46.579 46.71 46.615 ;
     RECT  47.484 39.341 49.158 46.615 ;
     RECT  43.704 46.615 49.158 46.921 ;
     RECT  43.704 46.921 49.23 47.035 ;
     RECT  49.968 46.309 52.722 47.035 ;
     RECT  38.196 46.615 39.402 47.191 ;
     RECT  40.215 46.535 42.75 47.191 ;
     RECT  43.704 47.035 52.722 47.191 ;
     RECT  37.584 47.191 39.402 47.281 ;
     RECT  40.215 47.191 52.722 47.281 ;
     RECT  36.828 46.747 36.846 47.315 ;
     RECT  53.568 36.481 54.198 47.317 ;
     RECT  37.584 47.281 52.722 47.389 ;
     RECT  53.568 47.317 54.702 47.389 ;
     RECT  37.584 47.389 54.702 47.461 ;
     RECT  37.044 47.461 54.846 47.579 ;
     RECT  37.764 47.579 54.846 47.695 ;
     RECT  37.764 47.695 54.882 47.731 ;
     RECT  37.764 47.731 55.134 48.541 ;
     RECT  37.764 48.541 55.206 48.659 ;
     RECT  37.764 48.659 43.074 48.695 ;
     RECT  37.764 48.695 43.038 48.739 ;
     RECT  37.584 48.739 43.038 48.767 ;
     RECT  37.584 48.767 42.966 48.775 ;
     RECT  44.064 48.659 55.206 48.775 ;
     RECT  56.16 45.059 57.042 48.775 ;
     RECT  82.404 45.149 82.422 48.775 ;
     RECT  83.415 37.319 83.697 48.775 ;
     RECT  36.9 48.775 42.966 48.811 ;
     RECT  82.404 48.775 83.697 48.811 ;
     RECT  85.5 48.433 85.518 48.901 ;
     RECT  44.064 48.775 57.042 49.199 ;
     RECT  82.404 48.811 83.754 49.315 ;
     RECT  81.612 45.149 81.63 49.351 ;
     RECT  85.5 48.901 85.59 49.351 ;
     RECT  78.015 36.149 78.297 49.441 ;
     RECT  85.5 49.351 86.274 49.549 ;
     RECT  36.648 48.811 42.966 49.579 ;
     RECT  34.815 2.413 35.097 49.747 ;
     RECT  36.648 49.579 43.326 49.855 ;
     RECT  44.064 49.199 56.697 49.855 ;
     RECT  31.716 49.855 31.734 49.891 ;
     RECT  32.544 49.081 32.562 49.891 ;
     RECT  34.128 49.747 35.097 49.891 ;
     RECT  81.144 49.351 81.63 49.891 ;
     RECT  82.404 49.315 83.826 49.891 ;
     RECT  36.648 49.855 56.697 50.017 ;
     RECT  81.144 49.891 83.934 50.045 ;
     RECT  57.672 49.441 57.69 50.053 ;
     RECT  31.716 49.891 32.562 50.125 ;
     RECT  85.5 49.549 86.31 50.125 ;
     RECT  33.48 49.891 35.097 50.245 ;
     RECT  30.492 50.161 30.762 50.251 ;
     RECT  31.536 50.125 32.562 50.251 ;
     RECT  33.372 50.245 35.097 50.251 ;
     RECT  33.372 50.251 35.19 50.395 ;
     RECT  57.672 50.053 58.266 50.521 ;
     RECT  36.54 50.017 56.697 50.557 ;
     RECT  30.492 50.251 32.562 50.585 ;
     RECT  30.852 50.585 32.562 50.593 ;
     RECT  33.372 50.395 35.298 50.593 ;
     RECT  57.636 50.521 58.266 50.791 ;
     RECT  59.4 50.287 59.418 50.791 ;
     RECT  81.144 50.045 83.898 50.819 ;
     RECT  36.432 50.557 56.697 50.935 ;
     RECT  57.636 50.791 59.418 50.999 ;
     RECT  36.216 50.935 56.697 51.067 ;
     RECT  65.268 51.061 65.286 51.101 ;
     RECT  30.852 50.593 35.298 51.307 ;
     RECT  30.852 51.307 35.442 51.331 ;
     RECT  36.216 51.067 56.79 51.331 ;
     RECT  30.852 51.331 56.79 51.601 ;
     RECT  57.636 50.999 58.338 51.601 ;
     RECT  78.015 49.441 78.678 51.601 ;
     RECT  81.144 50.819 83.79 51.601 ;
     RECT  81.144 51.601 83.898 51.637 ;
     RECT  30.852 51.601 58.338 51.665 ;
     RECT  65.556 51.241 65.574 51.677 ;
     RECT  80.604 51.637 83.898 51.677 ;
     RECT  81.144 51.677 83.898 51.701 ;
     RECT  78.015 51.601 78.75 51.773 ;
     RECT  81.504 51.701 83.898 51.781 ;
     RECT  78.015 51.773 78.678 51.809 ;
     RECT  85.5 50.125 86.346 51.809 ;
     RECT  36.36 51.665 58.338 51.935 ;
     RECT  29.415 2.413 29.697 52.015 ;
     RECT  30.852 51.665 35.55 52.015 ;
     RECT  36.36 51.935 40.734 52.043 ;
     RECT  81.504 51.781 84.114 52.051 ;
     RECT  85.5 51.809 86.274 52.109 ;
     RECT  81.504 52.051 84.402 52.249 ;
     RECT  85.5 52.109 86.166 52.249 ;
     RECT  81.504 52.249 86.166 52.301 ;
     RECT  41.724 51.935 58.338 52.349 ;
     RECT  84.924 52.301 86.166 52.397 ;
     RECT  84.924 52.397 85.518 52.493 ;
     RECT  45.036 52.349 58.338 52.519 ;
     RECT  59.4 50.999 59.418 52.519 ;
     RECT  84.96 52.493 85.518 52.589 ;
     RECT  81.504 52.301 84.114 52.781 ;
     RECT  36.36 52.043 40.59 52.825 ;
     RECT  36.36 52.825 40.914 52.861 ;
     RECT  41.724 52.349 44.298 52.861 ;
     RECT  29.415 52.015 35.55 53.035 ;
     RECT  45.036 52.519 59.418 53.035 ;
     RECT  29.415 53.035 35.586 53.038 ;
     RECT  30.492 53.038 35.586 53.131 ;
     RECT  36.36 52.861 44.298 53.131 ;
     RECT  45.036 53.035 59.67 53.131 ;
     RECT  61.815 2.413 62.097 53.257 ;
     RECT  78.015 51.809 78.297 53.257 ;
     RECT  81.504 52.781 83.898 53.321 ;
     RECT  30.492 53.131 59.67 53.401 ;
     RECT  86.292 53.227 86.31 53.419 ;
     RECT  78.015 53.257 78.678 53.429 ;
     RECT  30.492 53.401 60.354 53.491 ;
     RECT  85.068 52.589 85.518 53.611 ;
     RECT  30.492 53.491 60.498 53.671 ;
     RECT  84.888 53.611 85.518 53.707 ;
     RECT  86.256 53.419 86.31 53.707 ;
     RECT  84.888 53.707 86.31 53.896 ;
     RECT  84.852 53.896 86.31 54.103 ;
     RECT  30.492 53.671 60.57 54.211 ;
     RECT  81.504 53.321 83.862 54.445 ;
     RECT  30.492 54.211 60.642 54.481 ;
     RECT  84.852 54.103 86.382 54.599 ;
     RECT  84.852 54.599 84.87 54.671 ;
     RECT  29.415 53.038 29.697 54.679 ;
     RECT  30.492 54.481 60.678 54.679 ;
     RECT  64.368 52.213 64.386 54.841 ;
     RECT  81.504 54.445 83.934 54.913 ;
     RECT  29.415 54.679 60.678 54.949 ;
     RECT  61.452 53.257 62.097 54.949 ;
     RECT  29.415 54.949 62.097 55.147 ;
     RECT  81.504 54.913 84.006 55.409 ;
     RECT  29.412 55.147 62.097 55.525 ;
     RECT  29.088 55.525 62.097 55.921 ;
     RECT  28.692 55.921 62.097 55.955 ;
     RECT  78.015 53.429 78.297 55.993 ;
     RECT  78.015 55.993 78.75 56.129 ;
     RECT  86.076 54.599 86.382 56.219 ;
     RECT  86.148 56.219 86.382 56.399 ;
     RECT  81.504 55.409 83.934 56.489 ;
     RECT  28.692 55.955 54.594 56.731 ;
     RECT  55.332 55.955 62.097 56.731 ;
     RECT  81.504 56.489 83.754 56.759 ;
     RECT  28.692 56.731 62.097 56.767 ;
     RECT  28.548 56.767 62.097 56.831 ;
     RECT  28.548 56.831 60.57 56.911 ;
     RECT  61.452 56.831 62.097 57.029 ;
     RECT  86.184 56.399 86.382 57.029 ;
     RECT  27.432 56.911 60.57 57.037 ;
     RECT  86.184 57.029 86.202 57.299 ;
     RECT  63.468 57.415 63.486 57.451 ;
     RECT  63.468 57.451 63.522 57.569 ;
     RECT  27.18 57.037 60.57 57.577 ;
     RECT  27.18 57.577 60.786 57.595 ;
     RECT  26.604 57.595 60.786 57.685 ;
     RECT  26.028 57.685 60.786 58.351 ;
     RECT  61.524 57.029 62.097 58.351 ;
     RECT  81.504 56.759 83.697 58.379 ;
     RECT  26.028 58.351 62.097 58.495 ;
     RECT  25.992 58.495 62.097 58.531 ;
     RECT  24.015 2.413 24.297 58.765 ;
     RECT  25.02 58.531 25.038 58.765 ;
     RECT  25.992 58.531 62.694 58.927 ;
     RECT  25.92 58.927 62.694 59.035 ;
     RECT  24.015 58.765 25.038 59.071 ;
     RECT  25.776 59.035 62.694 59.071 ;
     RECT  24.015 59.071 62.694 59.233 ;
     RECT  63.468 57.569 63.486 59.233 ;
     RECT  24.015 59.233 63.486 59.305 ;
     RECT  64.26 54.841 64.386 59.305 ;
     RECT  24.015 59.305 64.386 59.495 ;
     RECT  24.015 59.495 25.182 60.385 ;
     RECT  26.064 59.495 64.386 60.385 ;
     RECT  24.015 60.385 64.386 60.719 ;
     RECT  81.504 58.379 81.954 60.809 ;
     RECT  32.04 60.719 64.386 60.989 ;
     RECT  24.015 60.719 31.302 61.501 ;
     RECT  32.04 60.989 64.314 61.501 ;
     RECT  24.015 61.501 64.314 62.581 ;
     RECT  24.015 62.581 64.386 63.779 ;
     RECT  24.015 63.779 28.458 64.355 ;
     RECT  29.232 63.779 64.386 64.859 ;
     RECT  25.092 64.355 28.458 64.867 ;
     RECT  29.232 64.859 60.606 64.867 ;
     RECT  81.612 60.809 81.954 65.039 ;
     RECT  24.015 64.355 24.297 65.245 ;
     RECT  25.092 64.867 60.606 65.245 ;
     RECT  81.936 65.039 81.954 65.579 ;
     RECT  24.015 65.245 60.606 65.641 ;
     RECT  61.452 64.859 64.386 65.641 ;
     RECT  24.015 65.641 64.386 65.939 ;
     RECT  24.015 65.939 60.642 66.479 ;
     RECT  25.2 66.479 60.642 66.515 ;
     RECT  24.015 66.479 24.462 66.785 ;
     RECT  61.452 65.939 64.386 66.857 ;
     RECT  25.2 66.515 60.606 67.441 ;
     RECT  61.452 66.857 63.486 67.441 ;
     RECT  64.368 66.857 64.386 67.559 ;
     RECT  24.015 66.785 24.297 67.819 ;
     RECT  25.2 67.441 63.486 67.819 ;
     RECT  24.015 67.819 63.486 68.392 ;
     RECT  25.128 68.392 63.486 68.521 ;
     RECT  25.128 68.521 63.594 68.639 ;
     RECT  64.368 68.791 64.386 68.981 ;
     RECT  24.015 68.392 24.297 69.835 ;
     RECT  25.128 68.639 63.486 69.835 ;
     RECT  24.015 69.835 63.486 70.025 ;
     RECT  24.015 70.025 63.414 70.109 ;
     RECT  25.128 70.109 63.414 70.367 ;
     RECT  25.56 70.367 63.414 71.491 ;
     RECT  25.56 71.491 63.486 71.753 ;
     RECT  25.56 71.753 63.414 72.391 ;
     RECT  83.196 58.379 83.697 72.689 ;
     RECT  64.224 72.661 64.242 73.229 ;
     RECT  25.416 72.391 63.414 73.499 ;
     RECT  25.668 73.499 63.414 73.805 ;
     RECT  25.992 73.805 63.414 74.659 ;
     RECT  25.956 74.659 63.414 75.235 ;
     RECT  25.668 75.235 63.414 75.631 ;
     RECT  25.272 75.631 63.414 75.677 ;
     RECT  25.668 75.677 63.414 75.731 ;
     RECT  25.668 75.731 62.262 75.803 ;
     RECT  63.396 75.731 63.414 75.803 ;
     RECT  25.668 75.803 62.19 76.505 ;
     RECT  25.776 76.505 62.19 76.819 ;
     RECT  25.776 76.819 62.226 77.009 ;
     RECT  25.776 77.009 25.794 77.395 ;
     RECT  25.632 77.395 25.794 77.501 ;
     RECT  25.704 77.501 25.794 77.791 ;
     RECT  26.568 77.009 62.226 77.791 ;
     RECT  25.704 77.791 62.226 78.089 ;
     RECT  26.316 78.089 62.226 78.161 ;
     RECT  26.316 78.161 62.19 79.213 ;
     RECT  26.316 79.213 62.334 79.243 ;
     RECT  26.136 79.243 62.334 79.439 ;
     RECT  26.316 79.439 62.097 79.781 ;
     RECT  26.82 79.781 62.097 80.087 ;
     RECT  26.892 80.087 62.097 80.333 ;
     RECT  27.36 80.333 62.097 80.825 ;
     RECT  52.272 80.825 62.097 80.933 ;
     RECT  52.452 80.933 62.097 81.059 ;
     RECT  52.452 81.059 60.57 81.329 ;
     RECT  52.452 81.329 60.426 81.365 ;
     RECT  27.36 80.825 51.462 81.715 ;
     RECT  52.452 81.365 60.246 81.743 ;
     RECT  61.344 81.059 62.097 81.743 ;
     RECT  27.36 81.715 51.606 81.751 ;
     RECT  52.452 81.743 59.022 81.751 ;
     RECT  27.36 81.751 59.022 81.905 ;
     RECT  58.392 81.905 59.022 82.175 ;
     RECT  59.76 81.743 60.246 82.445 ;
     RECT  58.68 82.175 59.022 82.489 ;
     RECT  59.76 82.445 59.958 82.489 ;
     RECT  27.36 81.905 57.618 82.555 ;
     RECT  26.892 82.555 57.618 82.595 ;
     RECT  58.68 82.489 59.958 82.679 ;
     RECT  58.68 82.679 59.778 82.859 ;
     RECT  58.68 82.859 59.49 82.985 ;
     RECT  58.68 82.985 59.31 83.057 ;
     RECT  27.576 82.595 57.618 83.299 ;
     RECT  27.576 83.299 57.726 83.371 ;
     RECT  58.68 83.057 59.022 83.371 ;
     RECT  27.576 83.371 59.022 83.489 ;
     RECT  27.576 83.489 28.566 83.525 ;
     RECT  29.304 83.489 59.022 83.525 ;
     RECT  27.576 83.525 28.458 83.633 ;
     RECT  28.368 83.633 28.458 83.759 ;
     RECT  29.304 83.525 58.95 83.759 ;
     RECT  29.304 83.759 42.174 83.795 ;
     RECT  43.344 83.759 58.95 83.795 ;
     RECT  29.415 83.795 42.102 83.939 ;
     RECT  43.596 83.795 58.95 83.939 ;
     RECT  2.415 28.985 2.697 83.987 ;
     RECT  7.815 2.413 8.097 83.987 ;
     RECT  13.215 2.413 13.497 83.987 ;
     RECT  18.615 2.413 18.897 83.987 ;
     RECT  24.015 70.109 24.297 83.987 ;
     RECT  61.815 81.743 62.097 83.987 ;
     RECT  67.215 2.413 67.497 83.987 ;
     RECT  72.615 2.413 72.897 83.987 ;
     RECT  78.015 56.129 78.297 83.987 ;
     RECT  83.415 72.689 83.697 83.987 ;
     RECT  27.576 83.633 27.594 84.029 ;
     RECT  29.415 83.939 41.778 84.029 ;
     RECT  43.596 83.939 57.15 84.029 ;
     RECT  39.6 84.029 41.778 84.065 ;
     RECT  43.596 84.029 48.042 84.065 ;
     RECT  53.604 84.029 57.15 84.065 ;
     RECT  58.032 83.939 58.95 84.065 ;
     RECT  48.852 84.029 52.83 84.101 ;
     RECT  36.9 84.029 38.754 84.137 ;
     RECT  39.6 84.065 41.634 84.137 ;
     RECT  53.748 84.065 56.754 84.137 ;
     RECT  39.6 84.137 40.95 84.173 ;
     RECT  48.96 84.101 52.83 84.173 ;
     RECT  52.812 84.173 52.83 84.209 ;
     RECT  55.764 84.137 56.754 84.209 ;
     RECT  58.68 84.065 58.95 84.209 ;
     RECT  45.615 84.065 48.042 84.221 ;
     RECT  2.415 83.987 2.505 84.257 ;
     RECT  7.815 83.987 7.905 84.257 ;
     RECT  13.215 83.987 13.305 84.257 ;
     RECT  18.615 83.987 18.705 84.257 ;
     RECT  24.015 83.987 24.105 84.257 ;
     RECT  29.415 84.029 36.162 84.257 ;
     RECT  39.6 84.173 40.59 84.257 ;
     RECT  45.615 84.221 47.898 84.257 ;
     RECT  48.96 84.173 51.822 84.257 ;
     RECT  56.415 84.209 56.754 84.257 ;
     RECT  61.815 83.987 61.905 84.257 ;
     RECT  67.215 83.987 67.305 84.257 ;
     RECT  72.615 83.987 72.705 84.257 ;
     RECT  78.015 83.987 78.105 84.257 ;
     RECT  83.415 83.987 83.505 84.257 ;
     RECT  30.06 84.257 34.434 84.299 ;
     RECT  36.9 84.137 37.602 84.299 ;
     RECT  39.6 84.257 39.618 84.299 ;
     RECT  53.748 84.137 53.802 84.299 ;
     RECT  56.736 84.257 56.754 84.299 ;
     RECT  30.06 84.299 33.966 84.317 ;
     RECT  35.424 84.257 36.162 84.365 ;
     RECT  43.596 84.065 44.262 84.365 ;
     RECT  45.756 84.257 47.898 84.365 ;
     RECT  48.96 84.257 50.886 84.365 ;
     RECT  36.9 84.299 36.918 84.371 ;
     RECT  38.664 84.137 38.754 84.371 ;
     RECT  40.572 84.257 40.59 84.371 ;
     RECT  54.72 84.137 54.738 84.371 ;
     RECT  58.68 84.209 58.698 84.371 ;
     RECT  45.756 84.365 47.214 84.413 ;
     RECT  48.96 84.365 48.978 84.941 ;
     RECT  30.06 84.317 32.994 85.517 ;
     RECT  50.076 84.365 50.094 85.517 ;
     RECT  30.06 85.517 30.474 85.565 ;
     RECT  43.596 84.365 43.83 85.565 ;
     RECT  30.06 85.565 30.078 85.613 ;
     RECT  45.972 84.413 47.214 85.661 ;
     RECT  33.948 84.317 33.966 85.675 ;
     RECT  33.948 85.675 34.182 85.723 ;
     RECT  45.972 85.661 45.99 85.771 ;
     RECT  33.948 85.723 34.254 85.901 ;
     RECT  45.288 85.771 45.99 85.949 ;
     RECT  31.284 85.517 32.994 86.045 ;
     RECT  32.04 86.045 32.994 86.093 ;
     RECT  45.468 85.949 45.99 86.093 ;
     RECT  48.564 86.107 48.582 86.155 ;
     RECT  32.148 86.093 32.994 86.189 ;
     RECT  32.328 86.189 32.994 86.203 ;
     RECT  32.328 86.203 33.21 86.237 ;
     RECT  48.564 86.155 48.654 86.237 ;
     RECT  53.748 84.299 53.766 86.237 ;
     RECT  31.284 86.045 31.302 86.285 ;
     RECT  32.328 86.237 32.346 86.285 ;
     RECT  33.948 85.901 34.074 86.285 ;
     RECT  35.46 84.365 36.162 86.285 ;
     RECT  45.972 86.093 45.99 86.285 ;
     RECT  46.98 85.661 47.214 86.285 ;
     RECT  48.636 86.237 48.654 86.285 ;
     RECT  51.804 84.257 51.822 86.285 ;
     RECT  33.192 86.237 33.21 86.381 ;
     RECT  36.144 86.285 36.162 86.381 ;
     RECT  43.812 85.565 43.83 86.381 ;
     RECT  46.98 86.285 46.998 86.381 ;
    LAYER M4 ;
     RECT  0.06 28.08 0.227 28.392 ;
     RECT  0.227 28.272 2.408 28.392 ;
     RECT  0.181 60.096 2.408 60.12 ;
     RECT  2.408 2.148 2.512 84.252 ;
     RECT  2.512 2.418 2.704 83.982 ;
     RECT  2.704 28.272 7.808 28.296 ;
     RECT  2.704 60.096 7.808 60.12 ;
     RECT  7.808 2.148 7.912 84.252 ;
     RECT  7.912 2.418 8.104 83.982 ;
     RECT  8.104 28.272 13.208 28.296 ;
     RECT  8.104 60.096 13.208 60.12 ;
     RECT  13.208 2.148 13.312 84.252 ;
     RECT  13.312 2.418 13.504 83.982 ;
     RECT  13.504 28.272 18.608 28.296 ;
     RECT  13.504 60.096 18.608 60.12 ;
     RECT  18.608 2.148 18.712 84.252 ;
     RECT  18.712 2.418 18.904 83.982 ;
     RECT  18.904 28.272 24.008 28.296 ;
     RECT  18.904 60.096 24.008 60.12 ;
     RECT  24.008 2.148 24.112 84.252 ;
     RECT  24.112 2.418 24.304 83.982 ;
     RECT  24.304 61.536 24.797 63.24 ;
     RECT  24.304 66.096 24.833 68.376 ;
     RECT  24.833 66.72 24.905 68.376 ;
     RECT  24.797 61.536 25.265 62.808 ;
     RECT  25.265 61.584 25.276 62.808 ;
     RECT  24.304 70.08 25.589 70.104 ;
     RECT  24.304 64.32 25.621 64.344 ;
     RECT  25.276 61.584 25.667 61.608 ;
     RECT  25.621 77.472 25.693 77.496 ;
     RECT  25.693 77.472 25.733 77.688 ;
     RECT  24.304 59.232 25.909 60.456 ;
     RECT  25.621 63.888 25.981 64.344 ;
     RECT  24.905 66.72 25.981 67.08 ;
     RECT  24.905 68.208 25.981 68.376 ;
     RECT  25.909 58.944 26.012 60.456 ;
     RECT  25.981 66.72 26.021 68.376 ;
     RECT  25.276 62.784 26.129 62.808 ;
     RECT  24.304 75.648 26.269 75.672 ;
     RECT  26.012 58.128 26.305 60.456 ;
     RECT  26.021 66.72 26.417 67.8 ;
     RECT  26.269 75.648 26.435 76.104 ;
     RECT  26.305 58.128 26.593 60.84 ;
     RECT  25.981 63.888 26.633 64.728 ;
     RECT  26.593 57.6 26.741 60.84 ;
     RECT  26.633 64.704 26.809 64.728 ;
     RECT  25.405 72.912 26.809 72.936 ;
     RECT  26.125 79.248 26.869 79.272 ;
     RECT  26.869 79.248 26.881 80.232 ;
     RECT  26.809 72.912 26.915 73.224 ;
     RECT  26.876 82.56 26.917 82.584 ;
     RECT  26.917 82.56 26.963 82.68 ;
     RECT  26.881 79.248 26.965 80.328 ;
     RECT  25.733 77.664 27.025 77.688 ;
     RECT  26.965 79.248 27.025 79.752 ;
     RECT  26.741 59.472 27.068 60.84 ;
     RECT  27.068 59.472 27.109 60.984 ;
     RECT  26.809 64.704 27.209 65.16 ;
     RECT  26.741 57.6 27.317 58.44 ;
     RECT  27.025 77.664 27.347 79.752 ;
     RECT  27.317 57.6 27.377 57.624 ;
     RECT  27.301 69.36 27.388 69.384 ;
     RECT  26.417 67.68 27.389 67.8 ;
     RECT  26.233 74.592 27.389 74.616 ;
     RECT  27.377 56.976 27.461 57.624 ;
     RECT  27.109 59.472 27.497 61.608 ;
     RECT  27.301 70.704 27.601 70.728 ;
     RECT  26.435 75.648 27.605 75.672 ;
     RECT  27.347 79.248 27.605 79.752 ;
     RECT  27.389 67.776 27.731 67.8 ;
     RECT  27.601 70.704 27.731 71.304 ;
     RECT  27.497 59.472 27.733 60.696 ;
     RECT  27.733 58.608 27.82 60.696 ;
     RECT  27.209 64.704 27.889 64.728 ;
     RECT  27.731 70.704 27.893 71.256 ;
     RECT  27.893 71.232 27.965 71.256 ;
     RECT  27.605 79.536 27.997 79.752 ;
     RECT  26.915 72.912 28.141 72.936 ;
     RECT  27.82 59.472 28.145 60.696 ;
     RECT  28.105 66.192 28.285 66.216 ;
     RECT  27.461 57.024 28.357 57.624 ;
     RECT  26.963 82.656 28.357 82.68 ;
     RECT  27.889 64.32 28.364 64.728 ;
     RECT  27.685 69.264 28.393 69.288 ;
     RECT  26.917 81.408 28.397 81.432 ;
     RECT  28.357 57.024 28.453 57.864 ;
     RECT  28.393 68.352 28.463 69.288 ;
     RECT  28.357 82.656 28.465 83.208 ;
     RECT  28.141 72.48 28.753 72.936 ;
     RECT  28.285 66.192 28.789 66.6 ;
     RECT  28.069 75.6 28.825 75.624 ;
     RECT  28.145 59.472 28.997 60.504 ;
     RECT  28.789 66.192 29.029 66.84 ;
     RECT  28.463 68.352 29.029 69.528 ;
     RECT  28.537 62.976 29.221 63 ;
     RECT  28.753 72.48 29.269 73.512 ;
     RECT  28.825 74.976 29.269 75.624 ;
     RECT  28.453 56.352 29.365 57.864 ;
     RECT  28.997 59.232 29.365 60.504 ;
     RECT  24.304 28.272 29.408 28.296 ;
     RECT  29.401 55.152 29.408 55.176 ;
     RECT  29.365 56.352 29.408 60.504 ;
     RECT  29.221 62.976 29.408 63.288 ;
     RECT  28.364 64.32 29.408 65.112 ;
     RECT  29.029 66.192 29.408 69.528 ;
     RECT  29.293 70.608 29.408 70.632 ;
     RECT  29.269 72.048 29.408 73.512 ;
     RECT  29.269 74.592 29.408 75.96 ;
     RECT  27.347 77.664 29.408 77.688 ;
     RECT  27.997 79.536 29.408 80.136 ;
     RECT  28.465 82.224 29.408 83.208 ;
     RECT  29.408 2.148 29.512 84.252 ;
     RECT  29.512 2.418 29.704 83.982 ;
     RECT  29.704 79.056 29.881 80.232 ;
     RECT  29.704 81.264 29.881 81.48 ;
     RECT  29.704 71.472 29.909 72.84 ;
     RECT  29.704 82.704 29.981 83.256 ;
     RECT  29.704 68.688 30.125 70.056 ;
     RECT  29.704 61.584 30.22 67.704 ;
     RECT  30.22 62.016 30.233 67.704 ;
     RECT  29.704 74.064 30.233 75.816 ;
     RECT  30.233 65.808 30.371 67.704 ;
     RECT  30.233 62.016 30.377 64.728 ;
     RECT  30.371 66.576 30.413 67.704 ;
     RECT  30.049 85.584 30.445 85.608 ;
     RECT  30.233 74.064 30.449 74.712 ;
     RECT  29.704 55.152 30.521 55.176 ;
     RECT  29.704 52.992 30.556 53.784 ;
     RECT  29.981 82.704 30.557 82.728 ;
     RECT  30.377 63.264 30.629 64.728 ;
     RECT  30.449 74.448 30.629 74.712 ;
     RECT  30.445 85.536 30.661 85.608 ;
     RECT  29.909 71.472 30.668 72.552 ;
     RECT  30.125 69.264 30.671 70.056 ;
     RECT  29.881 79.056 30.697 79.752 ;
     RECT  29.704 76.848 30.737 76.92 ;
     RECT  30.668 71.328 30.755 72.552 ;
     RECT  30.661 85.488 30.757 85.608 ;
     RECT  30.629 63.792 30.809 64.728 ;
     RECT  30.809 63.792 30.845 64.344 ;
     RECT  30.757 85.488 30.853 86.088 ;
     RECT  29.704 59.472 30.877 60.408 ;
     RECT  30.755 71.808 30.917 72.552 ;
     RECT  29.881 81.456 30.989 81.48 ;
     RECT  29.704 58.032 31.052 58.056 ;
     RECT  30.877 59.04 31.052 60.408 ;
     RECT  30.671 69.264 31.061 70.152 ;
     RECT  31.052 51.312 31.093 51.336 ;
     RECT  30.556 52.992 31.093 53.016 ;
     RECT  30.853 85.488 31.133 86.184 ;
     RECT  31.093 51.312 31.139 53.016 ;
     RECT  31.061 69.264 31.201 69.72 ;
     RECT  30.377 62.016 31.205 62.04 ;
     RECT  31.133 85.536 31.229 86.184 ;
     RECT  31.229 85.536 31.235 86.28 ;
     RECT  30.629 74.448 31.277 74.568 ;
     RECT  31.201 69.024 31.313 69.72 ;
     RECT  31.093 73.2 31.331 73.224 ;
     RECT  31.333 84.336 31.381 84.36 ;
     RECT  31.052 58.032 31.489 60.408 ;
     RECT  30.697 78.624 31.493 79.752 ;
     RECT  30.917 71.808 31.601 71.832 ;
     RECT  31.493 79.68 31.621 79.752 ;
     RECT  31.525 55.824 31.633 55.848 ;
     RECT  29.704 57.024 31.633 57.048 ;
     RECT  31.139 51.936 31.673 53.016 ;
     RECT  30.413 66.576 31.717 66.6 ;
     RECT  30.413 67.68 31.717 67.704 ;
     RECT  30.845 64.224 31.877 64.344 ;
     RECT  31.673 51.936 31.907 52.44 ;
     RECT  31.777 63.024 31.909 63.048 ;
     RECT  31.877 64.224 31.909 65.016 ;
     RECT  31.621 79.68 31.916 79.8 ;
     RECT  31.237 80.784 31.916 80.808 ;
     RECT  31.909 63.024 31.961 65.016 ;
     RECT  30.737 76.896 31.997 76.92 ;
     RECT  31.493 78.624 32.069 78.696 ;
     RECT  31.907 51.936 32.177 51.96 ;
     RECT  31.916 79.68 32.195 80.808 ;
     RECT  31.235 85.92 32.245 86.28 ;
     RECT  31.381 83.808 32.249 84.36 ;
     RECT  32.245 85.488 32.341 86.28 ;
     RECT  31.633 55.824 32.353 57.048 ;
     RECT  31.489 58.032 32.353 60.456 ;
     RECT  32.195 79.728 32.389 80.808 ;
     RECT  32.317 78.048 32.401 78.072 ;
     RECT  32.249 83.808 32.425 84.12 ;
     RECT  32.341 85.392 32.428 86.28 ;
     RECT  31.717 66.576 32.461 67.704 ;
     RECT  32.353 55.824 32.537 60.456 ;
     RECT  32.428 85.488 32.573 86.28 ;
     RECT  31.313 69.264 32.629 69.72 ;
     RECT  31.961 63.024 32.645 64.344 ;
     RECT  32.629 69.216 32.675 69.72 ;
     RECT  32.537 55.824 32.717 57.048 ;
     RECT  32.629 71.04 32.717 71.064 ;
     RECT  32.537 58.704 32.749 60.456 ;
     RECT  32.173 61.488 32.749 61.512 ;
     RECT  32.389 79.728 32.753 80.952 ;
     RECT  32.173 74.112 32.821 74.136 ;
     RECT  32.717 55.824 32.893 56.616 ;
     RECT  31.861 53.52 33.001 53.544 ;
     RECT  32.461 72.912 33.037 72.936 ;
     RECT  32.821 74.016 33.037 74.136 ;
     RECT  30.233 75.792 33.037 75.816 ;
     RECT  32.461 66.576 33.073 67.944 ;
     RECT  32.675 69.216 33.077 69.288 ;
     RECT  32.573 85.584 33.181 86.28 ;
     RECT  32.425 83.568 33.257 84.12 ;
     RECT  32.645 63.024 33.329 64.104 ;
     RECT  33.073 66 33.469 67.944 ;
     RECT  33.257 83.808 33.541 84.12 ;
     RECT  30.733 50.256 33.577 50.28 ;
     RECT  33.001 51.264 33.577 51.288 ;
     RECT  33.541 83.808 33.613 84.216 ;
     RECT  33.577 50.256 33.617 51.288 ;
     RECT  33.613 83.808 33.637 84.312 ;
     RECT  33.077 69.264 33.685 69.288 ;
     RECT  33.181 78.624 33.685 78.648 ;
     RECT  33.637 83.808 33.689 84.36 ;
     RECT  33.037 72.912 33.781 74.136 ;
     RECT  33.781 72.912 33.901 74.472 ;
     RECT  33.037 75.792 33.901 76.392 ;
     RECT  33.001 52.56 33.932 53.544 ;
     RECT  32.893 55.248 33.932 56.616 ;
     RECT  33.932 52.56 33.937 56.616 ;
     RECT  32.749 58.704 33.973 61.512 ;
     RECT  33.901 72.912 34.009 76.392 ;
     RECT  33.329 63.12 34.045 64.104 ;
     RECT  34.045 63.12 34.069 64.2 ;
     RECT  33.469 65.76 34.069 67.944 ;
     RECT  32.753 79.728 34.069 80.808 ;
     RECT  34.009 72.912 34.081 76.776 ;
     RECT  33.685 69.264 34.117 69.432 ;
     RECT  33.685 78.624 34.117 78.696 ;
     RECT  34.069 79.728 34.117 81.096 ;
     RECT  34.081 72.912 34.172 77.16 ;
     RECT  34.172 72.576 34.261 77.16 ;
     RECT  34.117 78.624 34.261 81.096 ;
     RECT  33.181 85.584 34.355 86.376 ;
     RECT  33.973 58.128 34.357 61.512 ;
     RECT  33.793 70.848 34.453 70.872 ;
     RECT  34.453 70.56 34.508 70.872 ;
     RECT  34.355 85.92 34.547 86.376 ;
     RECT  34.069 63.12 34.549 67.944 ;
     RECT  34.117 68.976 34.549 69.432 ;
     RECT  34.547 86.016 34.643 86.376 ;
     RECT  34.549 63.12 34.685 69.432 ;
     RECT  34.508 70.416 34.685 70.872 ;
     RECT  34.685 63.12 34.693 70.872 ;
     RECT  29.704 28.272 34.808 28.296 ;
     RECT  33.617 50.352 34.808 51.288 ;
     RECT  33.937 52.56 34.808 57.048 ;
     RECT  34.357 58.128 34.808 61.944 ;
     RECT  34.693 63.12 34.808 71.496 ;
     RECT  34.261 72.576 34.808 81.096 ;
     RECT  33.061 82.464 34.808 82.488 ;
     RECT  33.689 84.144 34.808 84.36 ;
     RECT  34.808 2.148 34.912 84.36 ;
     RECT  34.912 2.418 35.104 84.36 ;
     RECT  35.104 62.784 35.201 62.808 ;
     RECT  35.104 56.352 35.219 57.624 ;
     RECT  35.104 72.288 35.219 74.472 ;
     RECT  35.104 77.424 35.267 80.28 ;
     RECT  34.643 86.112 35.267 86.376 ;
     RECT  35.104 59.04 35.417 61.176 ;
     RECT  35.104 82.464 35.453 84.36 ;
     RECT  35.104 63.84 35.489 69.864 ;
     RECT  35.267 86.256 35.489 86.376 ;
     RECT  35.489 65.76 35.507 69.864 ;
     RECT  35.453 82.464 35.525 83.784 ;
     RECT  35.489 63.84 35.633 64.2 ;
     RECT  35.104 76.32 35.669 76.344 ;
     RECT  35.507 65.76 35.705 69.336 ;
     RECT  35.267 77.952 35.885 80.28 ;
     RECT  35.885 78.624 35.957 80.28 ;
     RECT  35.417 61.152 36.137 61.176 ;
     RECT  35.489 86.352 36.173 86.376 ;
     RECT  35.104 53.04 36.229 54.36 ;
     RECT  36.181 81.456 36.268 81.48 ;
     RECT  35.104 50.352 36.349 51.336 ;
     RECT  36.229 52.32 36.349 54.36 ;
     RECT  36.349 50.352 36.421 54.36 ;
     RECT  35.219 73.776 36.421 74.472 ;
     RECT  36.421 50.064 36.461 54.36 ;
     RECT  35.104 71.28 36.461 71.304 ;
     RECT  35.417 59.04 36.493 60.12 ;
     RECT  35.219 72.288 36.529 72.36 ;
     RECT  36.461 53.136 36.533 54.36 ;
     RECT  35.525 82.464 36.565 83.4 ;
     RECT  36.565 82.464 36.605 83.64 ;
     RECT  36.605 83.376 36.637 83.64 ;
     RECT  35.219 56.352 36.709 57.096 ;
     RECT  36.493 58.32 36.709 60.12 ;
     RECT  36.533 53.76 36.745 54.36 ;
     RECT  36.461 50.064 36.785 51.96 ;
     RECT  36.745 53.76 36.812 54.648 ;
     RECT  36.805 47.28 36.817 47.304 ;
     RECT  35.633 64.176 36.817 64.2 ;
     RECT  36.785 50.064 36.851 50.376 ;
     RECT  36.817 46.752 36.853 47.304 ;
     RECT  36.709 56.352 36.853 60.12 ;
     RECT  36.812 53.76 36.889 54.84 ;
     RECT  36.853 55.824 36.889 60.12 ;
     RECT  36.853 46.128 36.892 47.304 ;
     RECT  36.889 53.76 36.893 60.12 ;
     RECT  36.421 73.488 36.893 74.472 ;
     RECT  36.892 46.128 36.901 46.776 ;
     RECT  36.637 75.792 36.925 75.816 ;
     RECT  36.385 76.896 36.925 76.92 ;
     RECT  36.529 72.048 36.961 72.36 ;
     RECT  36.925 75.792 36.997 76.92 ;
     RECT  36.889 77.904 36.997 77.928 ;
     RECT  36.637 83.376 37.001 83.688 ;
     RECT  36.817 64.176 37.037 64.872 ;
     RECT  37.037 64.176 37.073 64.2 ;
     RECT  35.705 66.576 37.073 69.336 ;
     RECT  36.893 57.936 37.145 60.12 ;
     RECT  36.785 51.648 37.217 51.96 ;
     RECT  35.957 79.536 37.253 80.28 ;
     RECT  36.851 50.064 37.321 50.088 ;
     RECT  37.145 58.032 37.325 60.12 ;
     RECT  37.325 58.368 37.361 60.12 ;
     RECT  36.997 75.792 37.361 78.072 ;
     RECT  37.333 70.992 37.42 71.016 ;
     RECT  37.001 83.664 37.433 83.688 ;
     RECT  36.961 72.048 37.573 72.504 ;
     RECT  37.073 68.064 37.613 69.336 ;
     RECT  37.321 49.296 37.619 50.088 ;
     RECT  37.253 79.536 37.621 79.8 ;
     RECT  37.619 49.296 37.66 49.512 ;
     RECT  36.893 53.76 37.681 56.52 ;
     RECT  36.893 74.448 37.685 74.472 ;
     RECT  37.573 72.048 37.721 72.984 ;
     RECT  37.681 53.088 37.829 56.52 ;
     RECT  37.217 51.936 37.865 51.96 ;
     RECT  37.621 79.248 37.865 79.8 ;
     RECT  37.361 59.184 37.897 60.12 ;
     RECT  37.573 61.536 37.897 61.56 ;
     RECT  37.721 72.048 37.907 72.936 ;
     RECT  37.361 76.464 37.907 78.072 ;
     RECT  37.073 66.576 37.969 67.032 ;
     RECT  38.041 65.52 38.101 65.544 ;
     RECT  37.969 66.528 38.101 67.032 ;
     RECT  38.108 62.592 38.141 62.616 ;
     RECT  37.829 56.016 38.156 56.52 ;
     RECT  37.897 59.184 38.189 61.56 ;
     RECT  38.141 62.592 38.195 63.288 ;
     RECT  38.101 65.52 38.195 67.032 ;
     RECT  37.829 53.088 38.225 54.648 ;
     RECT  38.195 63.264 38.225 63.288 ;
     RECT  38.156 56.016 38.243 56.616 ;
     RECT  38.225 53.088 38.297 53.112 ;
     RECT  38.189 59.184 38.297 60.12 ;
     RECT  37.66 49.296 38.329 49.32 ;
     RECT  37.907 78.048 38.369 78.072 ;
     RECT  36.901 46.128 38.405 46.152 ;
     RECT  37.933 81.888 38.405 81.912 ;
     RECT  37.907 72.048 38.473 72.504 ;
     RECT  38.297 59.856 38.579 60.12 ;
     RECT  38.473 71.472 38.653 72.504 ;
     RECT  38.195 66.096 38.725 67.032 ;
     RECT  37.613 68.064 38.725 69.288 ;
     RECT  38.78 51.792 38.797 51.816 ;
     RECT  38.329 48.384 38.801 49.32 ;
     RECT  37.907 76.464 38.833 76.776 ;
     RECT  38.797 51.408 38.867 51.816 ;
     RECT  38.833 75.792 38.869 76.776 ;
     RECT  38.725 66.096 38.873 69.288 ;
     RECT  37.861 74.304 38.905 74.328 ;
     RECT  38.873 66.096 38.981 67.704 ;
     RECT  38.653 70.56 38.981 72.504 ;
     RECT  38.801 48.672 39.013 49.32 ;
     RECT  38.981 66.096 39.089 67.032 ;
     RECT  38.545 58.128 39.157 58.152 ;
     RECT  38.225 54.624 39.229 54.648 ;
     RECT  39.193 46.272 39.263 46.296 ;
     RECT  39.229 63.552 39.301 63.576 ;
     RECT  38.981 72.336 39.337 72.504 ;
     RECT  39.229 54.624 39.349 54.888 ;
     RECT  38.243 56.016 39.349 56.52 ;
     RECT  38.579 60 39.373 60.12 ;
     RECT  38.189 61.536 39.373 61.56 ;
     RECT  39.337 72.336 39.404 72.84 ;
     RECT  38.905 74.112 39.404 74.328 ;
     RECT  38.869 75.792 39.404 76.968 ;
     RECT  37.865 79.248 39.409 79.272 ;
     RECT  38.821 52.992 39.445 53.016 ;
     RECT  39.349 54.096 39.445 54.888 ;
     RECT  39.404 75.792 39.445 77.544 ;
     RECT  39.013 48.672 39.589 49.56 ;
     RECT  38.873 68.688 39.637 69.288 ;
     RECT  39.349 55.92 39.877 56.52 ;
     RECT  39.157 57.936 39.877 58.152 ;
     RECT  39.637 68.688 40.028 69.336 ;
     RECT  39.74 80.928 40.069 80.952 ;
     RECT  40.028 68.256 40.093 69.336 ;
     RECT  38.981 70.56 40.093 71.256 ;
     RECT  39.373 60 40.201 61.56 ;
     RECT  35.104 28.272 40.208 28.296 ;
     RECT  39.263 46.272 40.208 46.344 ;
     RECT  39.589 48.672 40.208 50.136 ;
     RECT  38.867 51.408 40.208 51.432 ;
     RECT  39.445 52.992 40.208 54.888 ;
     RECT  39.877 55.92 40.208 58.152 ;
     RECT  40.201 59.184 40.208 61.56 ;
     RECT  39.301 63.552 40.208 64.92 ;
     RECT  39.089 66.336 40.208 67.032 ;
     RECT  40.093 68.256 40.208 71.256 ;
     RECT  39.404 72.336 40.208 74.328 ;
     RECT  39.445 75.792 40.208 77.688 ;
     RECT  39.409 78.672 40.208 79.272 ;
     RECT  40.069 80.544 40.208 80.952 ;
     RECT  39.761 82.08 40.208 82.104 ;
     RECT  40.208 2.148 40.312 84.252 ;
     RECT  40.312 2.418 40.504 83.982 ;
     RECT  40.504 46.272 40.565 46.344 ;
     RECT  40.504 67.776 40.601 70.824 ;
     RECT  40.504 75.792 40.601 76.584 ;
     RECT  40.565 46.272 40.637 46.296 ;
     RECT  40.504 54.384 40.643 54.888 ;
     RECT  40.504 62.688 40.673 64.92 ;
     RECT  40.504 73.824 40.673 74.328 ;
     RECT  40.504 49.296 40.709 53.064 ;
     RECT  40.601 67.776 40.817 69.24 ;
     RECT  40.709 49.296 40.925 53.016 ;
     RECT  40.504 47.568 40.961 47.592 ;
     RECT  40.817 69.216 40.961 69.24 ;
     RECT  40.673 62.688 41.069 64.44 ;
     RECT  40.925 49.296 41.315 52.2 ;
     RECT  41.315 49.296 41.321 50.712 ;
     RECT  40.504 77.664 41.357 77.688 ;
     RECT  40.504 56.016 41.363 60.456 ;
     RECT  41.363 59.088 41.573 60.456 ;
     RECT  40.504 72.816 41.641 72.84 ;
     RECT  40.673 74.016 41.641 74.328 ;
     RECT  40.504 28.272 41.645 28.296 ;
     RECT  40.601 75.792 41.645 76.344 ;
     RECT  41.321 49.296 41.753 50.04 ;
     RECT  40.601 70.8 41.797 70.824 ;
     RECT  41.641 72.816 41.797 74.328 ;
     RECT  41.797 70.8 41.843 74.328 ;
     RECT  41.843 71.232 41.884 74.328 ;
     RECT  41.315 51.936 41.929 52.2 ;
     RECT  41.069 63.504 42.077 64.44 ;
     RECT  41.884 72.816 42.077 74.328 ;
     RECT  40.504 66.24 42.185 66.6 ;
     RECT  40.817 67.776 42.257 67.8 ;
     RECT  41.363 56.016 42.325 57.864 ;
     RECT  41.573 59.088 42.325 60.36 ;
     RECT  42.325 56.016 42.365 60.36 ;
     RECT  42.253 48.096 42.397 48.12 ;
     RECT  42.397 48.096 42.433 48.168 ;
     RECT  42.365 56.016 42.437 58.728 ;
     RECT  42.077 73.632 42.473 74.088 ;
     RECT  42.433 47.952 42.577 48.168 ;
     RECT  41.753 49.296 42.577 49.32 ;
     RECT  40.643 54.864 42.577 54.888 ;
     RECT  42.437 56.016 42.577 56.472 ;
     RECT  42.365 60 42.613 60.36 ;
     RECT  40.504 61.68 42.613 61.704 ;
     RECT  42.185 66.432 42.613 66.6 ;
     RECT  42.109 78.528 42.617 78.552 ;
     RECT  42.577 47.952 42.649 49.32 ;
     RECT  40.504 80.544 42.649 80.712 ;
     RECT  41.677 81.696 42.649 81.72 ;
     RECT  42.613 60 42.707 61.704 ;
     RECT  41.645 75.792 42.721 75.816 ;
     RECT  42.577 54.864 42.755 56.472 ;
     RECT  42.707 61.584 42.761 61.704 ;
     RECT  42.473 74.016 42.797 74.088 ;
     RECT  41.929 51.936 42.833 52.296 ;
     RECT  42.707 60 42.941 60.36 ;
     RECT  42.649 80.256 42.977 81.72 ;
     RECT  42.721 75.456 43.009 75.816 ;
     RECT  41.713 53.52 43.049 53.544 ;
     RECT  42.505 69.264 43.081 69.288 ;
     RECT  41.884 71.232 43.157 71.256 ;
     RECT  42.977 80.256 43.157 81.624 ;
     RECT  42.613 66.432 43.285 67.32 ;
     RECT  43.081 68.4 43.285 69.288 ;
     RECT  43.009 75.216 43.285 75.816 ;
     RECT  42.901 76.992 43.285 77.016 ;
     RECT  42.649 47.856 43.297 49.32 ;
     RECT  43.285 66.432 43.331 69.288 ;
     RECT  43.285 75.216 43.331 77.016 ;
     RECT  41.785 46.176 43.333 46.2 ;
     RECT  43.331 66.432 43.337 67.512 ;
     RECT  43.333 45.552 43.379 46.2 ;
     RECT  42.437 57.84 43.441 58.728 ;
     RECT  43.331 75.456 43.481 76.488 ;
     RECT  42.755 54.864 43.513 56.04 ;
     RECT  42.901 79.2 43.621 79.224 ;
     RECT  43.441 57.024 43.625 58.728 ;
     RECT  43.621 78.624 43.693 79.224 ;
     RECT  43.157 80.256 43.693 80.28 ;
     RECT  43.693 78.624 43.697 80.28 ;
     RECT  43.513 54.576 43.765 56.04 ;
     RECT  42.973 62.16 43.765 62.184 ;
     RECT  43.337 66.576 43.769 67.512 ;
     RECT  43.585 85.536 43.801 85.56 ;
     RECT  43.765 54.384 43.805 56.04 ;
     RECT  42.833 51.936 43.841 51.96 ;
     RECT  43.805 54.384 43.849 54.744 ;
     RECT  43.697 78.624 43.909 79.896 ;
     RECT  42.797 74.064 44.053 74.088 ;
     RECT  43.297 47.856 44.093 49.608 ;
     RECT  44.053 73.824 44.125 74.088 ;
     RECT  43.837 53.088 44.129 53.112 ;
     RECT  43.849 54.384 44.129 54.6 ;
     RECT  42.145 83.76 44.189 83.784 ;
     RECT  44.129 54.576 44.201 54.6 ;
     RECT  43.765 61.44 44.269 62.184 ;
     RECT  44.189 83.76 44.273 84.36 ;
     RECT  43.585 70.368 44.305 70.392 ;
     RECT  43.909 78.48 44.381 79.896 ;
     RECT  44.053 1.728 44.417 1.752 ;
     RECT  44.269 61.44 44.437 62.616 ;
     RECT  43.379 45.552 44.489 45.576 ;
     RECT  43.331 69.264 44.581 69.288 ;
     RECT  44.485 77.376 44.629 77.4 ;
     RECT  44.381 78.48 44.629 79.8 ;
     RECT  44.093 47.856 44.665 49.32 ;
     RECT  42.941 60 44.677 60.12 ;
     RECT  43.805 56.016 44.737 56.04 ;
     RECT  43.625 57.024 44.737 57.864 ;
     RECT  44.581 68.928 44.869 69.288 ;
     RECT  44.869 68.928 44.876 69.336 ;
     RECT  44.305 70.368 44.876 70.44 ;
     RECT  42.077 64.416 44.881 64.44 ;
     RECT  44.737 56.016 44.917 57.864 ;
     RECT  44.273 83.76 44.917 83.832 ;
     RECT  44.269 50.928 44.953 50.952 ;
     RECT  43.769 66.576 44.953 67.176 ;
     RECT  44.665 46.896 45.061 49.32 ;
     RECT  44.953 50.4 45.061 50.952 ;
     RECT  44.125 73.008 45.061 74.088 ;
     RECT  43.481 75.456 45.061 75.816 ;
     RECT  44.629 77.376 45.061 79.8 ;
     RECT  44.881 64.416 45.068 64.968 ;
     RECT  44.437 61.44 45.097 63.288 ;
     RECT  45.068 64.416 45.097 65.064 ;
     RECT  45.097 61.44 45.109 65.064 ;
     RECT  45.061 72.96 45.157 74.088 ;
     RECT  45.157 72.24 45.169 74.088 ;
     RECT  45.061 75.456 45.169 79.8 ;
     RECT  44.737 53.52 45.241 53.544 ;
     RECT  44.876 68.928 45.277 70.44 ;
     RECT  44.917 56.016 45.349 58.152 ;
     RECT  45.169 72.24 45.385 79.8 ;
     RECT  45.241 53.04 45.493 53.544 ;
     RECT  45.385 72.24 45.493 80.376 ;
     RECT  43.157 81.504 45.493 81.624 ;
     RECT  44.917 83.04 45.493 83.832 ;
     RECT  45.349 55.68 45.529 58.728 ;
     RECT  44.677 60 45.529 60.408 ;
     RECT  45.493 52.704 45.601 53.544 ;
     RECT  45.169 54.672 45.601 54.696 ;
     RECT  44.233 3.696 45.608 3.72 ;
     RECT  45.061 46.896 45.608 50.952 ;
     RECT  45.601 52.704 45.608 54.696 ;
     RECT  45.529 55.68 45.608 60.408 ;
     RECT  45.109 61.44 45.608 65.208 ;
     RECT  44.953 66.576 45.608 67.272 ;
     RECT  45.277 68.928 45.608 70.824 ;
     RECT  45.493 72.24 45.608 83.832 ;
     RECT  45.608 2.148 45.637 84.252 ;
     RECT  45.637 2.148 45.712 84.408 ;
     RECT  45.712 2.418 45.785 84.408 ;
     RECT  45.785 2.418 45.904 84.216 ;
     RECT  45.904 80.544 46.067 84.216 ;
     RECT  45.904 53.52 46.073 63.336 ;
     RECT  46.067 81.168 46.163 84.216 ;
     RECT  45.904 52.32 46.181 52.536 ;
     RECT  46.163 83.52 46.204 84.216 ;
     RECT  45.904 72.24 46.217 74.04 ;
     RECT  46.163 81.168 46.217 82.152 ;
     RECT  46.217 73.584 46.253 74.04 ;
     RECT  43.801 85.536 46.268 86.376 ;
     RECT  46.268 85.488 46.309 86.376 ;
     RECT  45.904 64.608 46.325 65.016 ;
     RECT  45.904 68.64 46.358 70.824 ;
     RECT  46.073 53.52 46.361 63.288 ;
     RECT  45.904 77.136 46.433 79.08 ;
     RECT  46.361 53.52 46.469 60.696 ;
     RECT  46.217 72.24 46.505 72.456 ;
     RECT  46.433 78.096 46.505 79.08 ;
     RECT  46.325 64.944 46.541 65.016 ;
     RECT  46.309 85.392 46.547 86.376 ;
     RECT  46.204 83.52 46.577 83.736 ;
     RECT  45.904 39.12 46.757 39.336 ;
     RECT  46.469 54.528 46.793 60.696 ;
     RECT  45.904 3.696 46.835 3.72 ;
     RECT  46.757 39.312 46.835 39.336 ;
     RECT  45.904 46.608 46.835 47.784 ;
     RECT  46.547 85.488 46.835 86.376 ;
     RECT  46.253 73.632 46.937 74.04 ;
     RECT  46.577 83.712 46.937 83.736 ;
     RECT  46.835 46.8 47.009 47.784 ;
     RECT  46.793 59.472 47.009 60.696 ;
     RECT  46.835 86.16 47.009 86.376 ;
     RECT  46.361 62.16 47.045 63.288 ;
     RECT  46.217 81.168 47.077 81.96 ;
     RECT  46.469 53.52 47.081 53.544 ;
     RECT  47.009 86.16 47.153 86.28 ;
     RECT  47.009 59.472 47.225 60.456 ;
     RECT  46.505 78.096 47.225 78.984 ;
     RECT  47.045 62.64 47.257 63.288 ;
     RECT  45.904 66.576 47.257 67.272 ;
     RECT  46.937 73.872 47.257 74.04 ;
     RECT  47.153 86.256 47.26 86.28 ;
     RECT  47.077 80.88 47.261 81.96 ;
     RECT  46.933 76.944 47.297 76.968 ;
     RECT  47.257 66.576 47.401 67.704 ;
     RECT  46.358 68.832 47.401 70.824 ;
     RECT  46.793 54.528 47.405 58.296 ;
     RECT  47.401 66.576 47.405 70.824 ;
     RECT  45.904 75.408 47.473 75.816 ;
     RECT  47.261 80.88 47.473 81.864 ;
     RECT  45.904 49.296 47.513 50.712 ;
     RECT  47.405 54.528 47.513 57.576 ;
     RECT  47.513 50.64 47.516 50.712 ;
     RECT  46.181 52.32 47.516 52.344 ;
     RECT  47.009 46.8 47.585 47.304 ;
     RECT  47.257 73.872 47.725 74.088 ;
     RECT  47.473 75.408 47.725 76.776 ;
     RECT  47.545 79.728 47.747 79.752 ;
     RECT  47.701 82.896 47.788 82.968 ;
     RECT  47.257 62.64 47.797 63.816 ;
     RECT  46.541 64.992 47.797 65.016 ;
     RECT  47.516 50.64 47.837 52.344 ;
     RECT  47.797 62.64 47.893 65.016 ;
     RECT  47.725 73.872 47.905 76.776 ;
     RECT  47.405 66.576 47.981 70.296 ;
     RECT  47.869 84.336 47.996 84.36 ;
     RECT  47.996 84.192 48.083 84.36 ;
     RECT  47.893 62.64 48.121 65.112 ;
     RECT  47.837 50.688 48.125 52.344 ;
     RECT  48.083 84.336 48.179 84.36 ;
     RECT  47.905 73.296 48.229 76.776 ;
     RECT  47.513 49.296 48.265 49.656 ;
     RECT  48.121 62.16 48.301 65.112 ;
     RECT  47.981 66.576 48.341 69.336 ;
     RECT  48.301 62.16 48.449 65.352 ;
     RECT  47.513 55.248 48.469 57.576 ;
     RECT  48.449 62.16 48.481 63.864 ;
     RECT  48.341 67.68 48.485 69.336 ;
     RECT  47.225 59.616 48.517 60.456 ;
     RECT  48.481 61.44 48.517 63.864 ;
     RECT  48.409 70.416 48.517 70.68 ;
     RECT  48.229 72 48.517 76.776 ;
     RECT  48.485 68.592 48.521 69.336 ;
     RECT  48.509 86.208 48.524 86.232 ;
     RECT  48.517 70.416 48.529 76.776 ;
     RECT  47.225 78.096 48.553 78.552 ;
     RECT  48.524 86.112 48.581 86.232 ;
     RECT  48.449 64.992 48.589 65.352 ;
     RECT  48.469 55.248 48.6 58.152 ;
     RECT  48.581 86.112 48.611 86.28 ;
     RECT  48.6 54.432 48.625 58.152 ;
     RECT  48.517 59.616 48.625 63.864 ;
     RECT  48.589 64.992 48.661 65.4 ;
     RECT  48.341 66.576 48.661 66.696 ;
     RECT  48.611 86.16 48.665 86.28 ;
     RECT  47.473 80.832 48.697 81.864 ;
     RECT  48.665 86.16 48.707 86.232 ;
     RECT  48.553 78.096 48.709 78.792 ;
     RECT  48.625 54.432 48.755 63.864 ;
     RECT  48.755 60.336 48.773 63.864 ;
     RECT  48.661 64.992 48.773 66.696 ;
     RECT  48.529 75.408 48.901 76.776 ;
     RECT  48.709 77.952 48.901 78.792 ;
     RECT  48.755 54.432 48.913 58.968 ;
     RECT  48.521 68.784 48.953 69.336 ;
     RECT  48.529 70.416 48.989 74.136 ;
     RECT  48.265 49.056 48.997 49.656 ;
     RECT  48.949 84.912 49.043 84.936 ;
     RECT  48.997 48.96 49.057 49.656 ;
     RECT  48.901 75.408 49.093 78.792 ;
     RECT  49.057 48.912 49.141 49.656 ;
     RECT  47.585 46.8 49.187 46.824 ;
     RECT  48.989 72 49.205 74.136 ;
     RECT  49.141 48.384 49.228 49.656 ;
     RECT  49.228 48.912 49.241 49.656 ;
     RECT  48.773 60.336 49.277 63.816 ;
     RECT  49.093 75.408 49.285 79.752 ;
     RECT  48.697 80.832 49.285 81.912 ;
     RECT  48.773 65.088 49.313 66.696 ;
     RECT  48.125 50.688 49.381 51.816 ;
     RECT  49.285 75.408 49.381 81.912 ;
     RECT  47.788 82.944 49.381 82.968 ;
     RECT  49.381 50.688 49.417 52.056 ;
     RECT  49.277 60.336 49.493 62.184 ;
     RECT  49.493 60.336 49.529 61.944 ;
     RECT  48.953 68.784 49.565 69.288 ;
     RECT  49.241 49.296 49.597 49.656 ;
     RECT  49.417 50.688 49.597 52.488 ;
     RECT  49.313 65.088 49.637 66.6 ;
     RECT  49.669 84.336 49.724 84.36 ;
     RECT  49.277 63.792 49.817 63.816 ;
     RECT  49.381 75.408 49.861 82.968 ;
     RECT  49.724 84.192 49.861 84.36 ;
     RECT  49.637 65.088 49.921 65.352 ;
     RECT  48.913 53.952 50.033 58.968 ;
     RECT  49.205 73.104 50.033 74.136 ;
     RECT  50.033 57.024 50.065 58.968 ;
     RECT  48.707 86.208 50.065 86.232 ;
     RECT  49.597 49.296 50.137 52.488 ;
     RECT  50.033 53.952 50.137 56.04 ;
     RECT  50.065 85.488 50.195 86.232 ;
     RECT  50.137 49.296 50.245 56.04 ;
     RECT  50.195 86.208 50.245 86.232 ;
     RECT  49.637 66.576 50.353 66.6 ;
     RECT  50.353 66.576 50.461 67.32 ;
     RECT  50.245 48.864 50.677 56.04 ;
     RECT  50.065 57.024 50.713 59.016 ;
     RECT  49.529 60.336 50.713 60.36 ;
     RECT  49.921 64.368 50.713 65.352 ;
     RECT  50.461 66.576 50.713 67.8 ;
     RECT  50.713 57.024 50.749 60.36 ;
     RECT  49.529 61.44 50.749 61.944 ;
     RECT  50.713 64.368 50.773 67.8 ;
     RECT  49.565 68.928 50.773 69.288 ;
     RECT  48.989 70.416 50.785 70.68 ;
     RECT  49.205 72 50.785 72.024 ;
     RECT  50.773 64.368 50.869 69.288 ;
     RECT  50.785 70.416 50.869 72.024 ;
     RECT  50.033 73.296 50.893 74.136 ;
     RECT  49.861 75.408 50.893 84.36 ;
     RECT  50.893 73.296 50.897 84.36 ;
     RECT  45.904 36.912 51.008 36.936 ;
     RECT  49.489 47.04 51.008 47.064 ;
     RECT  50.677 48.48 51.008 56.04 ;
     RECT  50.749 57.024 51.008 61.944 ;
     RECT  50.569 63.072 51.008 63.096 ;
     RECT  50.869 64.368 51.008 72.024 ;
     RECT  50.897 73.296 51.008 84.252 ;
     RECT  51.008 2.148 51.112 84.252 ;
     RECT  51.112 2.418 51.304 83.982 ;
     RECT  51.304 74.064 51.329 74.088 ;
     RECT  51.304 50.688 51.365 54.456 ;
     RECT  51.304 64.704 51.365 67.32 ;
     RECT  51.304 69.024 51.473 69.864 ;
     RECT  51.473 69.168 51.509 69.864 ;
     RECT  51.304 57.936 51.545 61.464 ;
     RECT  51.304 71.328 51.617 72.024 ;
     RECT  51.304 77.568 51.628 83.88 ;
     RECT  51.365 50.688 51.797 52.488 ;
     RECT  51.365 64.704 51.797 66.744 ;
     RECT  51.545 57.936 51.833 61.368 ;
     RECT  50.245 86.208 51.833 86.28 ;
     RECT  51.797 50.688 51.949 52.44 ;
     RECT  51.797 64.704 52.085 66.696 ;
     RECT  51.304 63.072 52.121 63.096 ;
     RECT  51.617 71.328 52.157 71.352 ;
     RECT  51.304 55.776 52.163 56.76 ;
     RECT  51.949 50.784 52.19 52.44 ;
     RECT  52.163 56.016 52.204 56.76 ;
     RECT  52.085 64.704 52.337 66.6 ;
     RECT  51.833 57.936 52.373 58.68 ;
     RECT  51.365 54.096 52.409 54.456 ;
     RECT  52.373 57.936 52.441 58.2 ;
     RECT  51.304 48.48 52.477 49.512 ;
     RECT  51.509 69.168 52.621 69.288 ;
     RECT  51.304 75.216 52.693 76.248 ;
     RECT  52.477 48.48 52.733 49.656 ;
     RECT  51.833 59.856 52.837 61.368 ;
     RECT  51.628 77.568 52.837 81.336 ;
     RECT  51.628 82.704 52.837 83.88 ;
     RECT  52.837 72.912 52.909 72.936 ;
     RECT  52.621 67.68 53.017 67.704 ;
     RECT  52.621 69.168 53.017 69.576 ;
     RECT  52.733 48.48 53.093 49.608 ;
     RECT  53.017 67.68 53.101 69.576 ;
     RECT  52.909 71.808 53.125 72.936 ;
     RECT  53.093 48.48 53.129 49.32 ;
     RECT  52.409 54.432 53.161 54.456 ;
     RECT  53.101 68.976 53.197 69.576 ;
     RECT  52.693 74.832 53.201 76.248 ;
     RECT  53.125 71.808 53.221 73.176 ;
     RECT  52.837 77.568 53.233 83.88 ;
     RECT  53.161 54.432 53.372 54.504 ;
     RECT  52.337 65.52 53.42 66.6 ;
     RECT  53.101 67.68 53.42 67.704 ;
     RECT  52.837 59.856 53.453 61.944 ;
     RECT  53.42 65.52 53.489 67.704 ;
     RECT  53.489 65.52 53.507 67.272 ;
     RECT  53.221 71.808 53.597 73.272 ;
     RECT  53.233 76.848 53.633 83.88 ;
     RECT  53.597 71.808 53.665 71.88 ;
     RECT  53.633 76.848 53.669 83.832 ;
     RECT  51.833 86.208 53.777 86.232 ;
     RECT  52.19 50.832 53.845 52.44 ;
     RECT  53.372 53.856 53.845 54.504 ;
     RECT  53.507 65.52 53.845 66.888 ;
     RECT  53.597 72.912 53.845 73.272 ;
     RECT  53.201 74.832 53.845 75.816 ;
     RECT  53.629 64.032 53.881 64.056 ;
     RECT  53.845 65.04 53.881 66.888 ;
     RECT  53.845 50.832 53.957 54.504 ;
     RECT  53.669 78.192 53.957 83.832 ;
     RECT  53.845 72.912 53.993 75.816 ;
     RECT  52.204 56.016 54.029 56.04 ;
     RECT  53.881 64.032 54.065 66.888 ;
     RECT  53.129 48.864 54.097 49.32 ;
     RECT  54.065 64.32 54.101 66.888 ;
     RECT  53.665 71.232 54.131 71.88 ;
     RECT  53.957 53.904 54.137 54.504 ;
     RECT  52.441 57.552 54.14 58.2 ;
     RECT  53.993 75.168 54.205 75.816 ;
     RECT  53.669 76.848 54.205 76.92 ;
     RECT  54.137 54.144 54.227 54.504 ;
     RECT  54.097 48.864 54.277 49.416 ;
     RECT  53.957 50.832 54.277 52.488 ;
     RECT  54.205 75.168 54.317 76.92 ;
     RECT  53.957 83.088 54.317 83.832 ;
     RECT  54.14 57.504 54.385 58.2 ;
     RECT  53.453 59.856 54.419 61.128 ;
     RECT  54.277 48.864 54.425 52.488 ;
     RECT  53.957 78.192 54.425 82.056 ;
     RECT  53.197 68.976 54.457 69.96 ;
     RECT  54.385 57.072 54.529 58.2 ;
     RECT  54.425 78.384 54.533 82.056 ;
     RECT  54.425 48.96 54.605 52.488 ;
     RECT  54.317 83.52 54.641 83.544 ;
     RECT  54.419 59.904 54.707 61.128 ;
     RECT  54.227 54.48 54.709 54.504 ;
     RECT  54.637 55.92 54.709 55.944 ;
     RECT  54.605 48.96 54.713 49.416 ;
     RECT  53.993 72.912 54.713 74.088 ;
     RECT  54.457 68.256 54.745 69.96 ;
     RECT  54.131 71.232 54.745 71.256 ;
     RECT  54.713 72.912 54.745 73.848 ;
     RECT  54.709 54.48 54.793 55.944 ;
     RECT  54.533 81.312 54.857 82.056 ;
     RECT  54.317 75.456 54.901 76.92 ;
     RECT  54.707 60.24 54.929 61.128 ;
     RECT  54.901 75.456 54.947 76.968 ;
     RECT  54.745 68.256 55.001 71.256 ;
     RECT  54.101 64.32 55.037 66.6 ;
     RECT  55.001 68.256 55.037 70.536 ;
     RECT  54.745 72.48 55.109 73.848 ;
     RECT  54.529 57.072 55.145 58.728 ;
     RECT  54.929 60.624 55.145 61.128 ;
     RECT  55.109 72.576 55.145 73.848 ;
     RECT  54.793 55.92 55.189 55.944 ;
     RECT  55.145 57.072 55.189 57.96 ;
     RECT  54.793 54.48 55.237 54.504 ;
     RECT  55.189 55.92 55.276 57.96 ;
     RECT  54.605 50.688 55.321 52.488 ;
     RECT  55.237 53.952 55.321 54.504 ;
     RECT  55.037 66.576 55.532 66.6 ;
     RECT  54.947 76.944 55.645 76.968 ;
     RECT  54.533 78.384 55.645 79.848 ;
     RECT  55.532 66.576 55.753 66.648 ;
     RECT  54.709 62.832 55.825 62.856 ;
     RECT  55.037 64.32 55.825 65.352 ;
     RECT  54.713 48.96 55.861 49.32 ;
     RECT  54.947 75.456 55.933 75.816 ;
     RECT  55.645 76.944 55.933 79.848 ;
     RECT  55.145 73.248 55.964 73.848 ;
     RECT  55.933 75.456 55.964 79.848 ;
     RECT  55.276 55.92 56.041 55.944 ;
     RECT  54.857 81.312 56.101 81.336 ;
     RECT  55.393 82.368 56.101 82.392 ;
     RECT  55.321 83.808 56.101 83.832 ;
     RECT  55.321 50.688 56.149 54.504 ;
     RECT  55.825 62.832 56.185 65.352 ;
     RECT  55.753 66.576 56.185 67.272 ;
     RECT  56.185 59.184 56.221 59.208 ;
     RECT  56.185 62.832 56.257 67.272 ;
     RECT  56.149 50.688 56.365 54.648 ;
     RECT  51.304 36.912 56.408 36.936 ;
     RECT  54.637 47.856 56.408 47.88 ;
     RECT  55.861 48.96 56.408 49.368 ;
     RECT  56.365 50.688 56.408 54.744 ;
     RECT  56.041 55.776 56.408 55.944 ;
     RECT  55.276 57.024 56.408 57.96 ;
     RECT  56.221 58.992 56.408 59.208 ;
     RECT  55.609 61.44 56.408 61.464 ;
     RECT  56.257 62.544 56.408 67.272 ;
     RECT  55.037 68.256 56.408 70.008 ;
     RECT  55.964 73.248 56.408 79.848 ;
     RECT  56.101 81.312 56.408 83.832 ;
     RECT  56.408 2.148 56.512 84.252 ;
     RECT  56.512 2.418 56.704 83.982 ;
     RECT  56.704 51.072 56.765 54.744 ;
     RECT  56.765 51.072 56.801 51.192 ;
     RECT  56.765 52.848 56.801 54.744 ;
     RECT  56.704 64.32 56.819 69.576 ;
     RECT  56.704 55.776 56.873 58.152 ;
     RECT  56.873 55.776 56.915 58.104 ;
     RECT  56.819 65.712 57.011 69.576 ;
     RECT  56.704 74.976 57.053 75.816 ;
     RECT  56.819 64.32 57.161 64.632 ;
     RECT  56.704 78.384 57.377 80.184 ;
     RECT  57.161 64.608 57.449 64.632 ;
     RECT  56.704 62.544 57.593 63.144 ;
     RECT  57.011 67.968 57.629 69.576 ;
     RECT  57.377 79.248 57.629 80.184 ;
     RECT  56.704 60.96 57.769 61.512 ;
     RECT  56.704 73.248 57.769 73.272 ;
     RECT  56.704 81.6 57.773 81.624 ;
     RECT  56.915 57.744 57.949 58.104 ;
     RECT  56.704 59.184 57.949 59.208 ;
     RECT  57.949 57.744 57.989 59.208 ;
     RECT  56.801 52.848 58.061 54.648 ;
     RECT  57.011 65.712 58.165 66.6 ;
     RECT  57.769 73.248 58.169 73.56 ;
     RECT  57.629 67.968 58.205 68.952 ;
     RECT  58.205 67.968 58.211 68.28 ;
     RECT  57.769 60.96 58.241 61.896 ;
     RECT  58.061 53.52 58.273 54.648 ;
     RECT  56.915 55.776 58.273 55.8 ;
     RECT  57.989 57.744 58.345 59.064 ;
     RECT  58.165 65.664 58.345 66.6 ;
     RECT  58.211 67.968 58.349 68.136 ;
     RECT  58.273 53.52 58.385 55.8 ;
     RECT  58.241 60.96 58.403 60.984 ;
     RECT  58.385 53.52 58.529 53.688 ;
     RECT  58.021 71.28 58.556 71.304 ;
     RECT  57.593 63.12 58.565 63.144 ;
     RECT  58.556 70.416 58.597 71.304 ;
     RECT  58.349 68.112 58.601 68.136 ;
     RECT  58.597 69.504 58.643 71.784 ;
     RECT  58.345 57.6 58.705 59.064 ;
     RECT  58.169 73.248 58.741 73.272 ;
     RECT  58.561 80.544 58.741 80.568 ;
     RECT  56.704 83.232 58.741 83.256 ;
     RECT  58.741 82.656 58.787 83.256 ;
     RECT  58.633 60.384 58.817 60.408 ;
     RECT  58.787 82.656 58.825 82.68 ;
     RECT  58.741 80.544 58.828 81.48 ;
     RECT  58.385 55.008 58.889 55.8 ;
     RECT  58.643 69.504 58.889 70.296 ;
     RECT  58.889 55.008 58.925 55.416 ;
     RECT  57.053 75.456 59.137 75.816 ;
     RECT  58.643 71.376 59.164 71.784 ;
     RECT  59.137 74.64 59.209 75.816 ;
     RECT  58.345 65.664 59.221 66.648 ;
     RECT  59.18 68.88 59.267 68.904 ;
     RECT  57.629 79.248 59.269 79.272 ;
     RECT  59.221 65.664 59.357 67.128 ;
     RECT  59.209 74.4 59.461 75.816 ;
     RECT  59.353 61.44 59.465 61.464 ;
     RECT  59.269 79.152 59.465 79.272 ;
     RECT  58.093 78 59.507 78.024 ;
     RECT  56.801 51.072 59.509 51.096 ;
     RECT  58.529 53.664 59.509 53.688 ;
     RECT  56.704 47.856 59.555 47.88 ;
     RECT  59.509 53.04 59.573 53.688 ;
     RECT  59.573 53.04 59.681 53.064 ;
     RECT  59.461 74.4 59.785 76.488 ;
     RECT  58.741 72.912 60.113 73.272 ;
     RECT  60.113 73.248 60.181 73.272 ;
     RECT  59.785 74.4 60.181 76.968 ;
     RECT  58.925 55.248 60.253 55.416 ;
     RECT  59.357 65.664 60.293 66.6 ;
     RECT  60.181 73.248 60.293 76.968 ;
     RECT  58.828 80.544 60.373 80.568 ;
     RECT  60.253 54.672 60.401 55.416 ;
     RECT  60.373 80.544 60.46 80.952 ;
     RECT  59.164 71.376 60.473 71.4 ;
     RECT  60.401 55.392 60.509 55.416 ;
     RECT  58.705 56.928 60.509 59.064 ;
     RECT  60.293 75.504 60.541 76.968 ;
     RECT  60.541 75.504 60.689 77.592 ;
     RECT  60.509 57.6 60.721 59.064 ;
     RECT  60.721 57.6 60.761 59.64 ;
     RECT  60.761 58.128 60.865 59.64 ;
     RECT  60.685 61.008 60.865 61.032 ;
     RECT  60.649 64.416 60.865 64.44 ;
     RECT  60.865 71.856 61.261 71.88 ;
     RECT  60.293 73.248 61.261 74.424 ;
     RECT  60.689 75.504 61.261 75.816 ;
     RECT  60.613 68.496 61.513 68.52 ;
     RECT  58.889 70.272 61.573 70.296 ;
     RECT  61.261 71.856 61.573 75.816 ;
     RECT  60.293 65.664 61.585 65.928 ;
     RECT  59.465 79.152 61.585 79.176 ;
     RECT  60.865 64.08 61.621 64.44 ;
     RECT  61.513 68.4 61.669 68.52 ;
     RECT  56.704 36.912 61.808 36.936 ;
     RECT  59.509 51.072 61.808 51.384 ;
     RECT  60.865 58.128 61.808 61.032 ;
     RECT  59.965 62.976 61.808 63 ;
     RECT  61.621 64.032 61.808 64.44 ;
     RECT  61.585 65.664 61.808 66.072 ;
     RECT  61.585 67.248 61.808 67.272 ;
     RECT  61.669 68.4 61.808 68.904 ;
     RECT  61.573 70.272 61.808 75.816 ;
     RECT  60.689 76.944 61.808 77.592 ;
     RECT  61.585 79.008 61.808 79.176 ;
     RECT  60.46 80.544 61.808 80.568 ;
     RECT  61.808 2.148 61.912 84.252 ;
     RECT  61.912 2.418 62.104 83.982 ;
     RECT  62.104 79.008 62.129 79.032 ;
     RECT  62.104 75.696 62.165 75.768 ;
     RECT  62.104 65.136 62.243 66.408 ;
     RECT  62.165 75.744 62.273 75.768 ;
     RECT  62.104 74.592 62.345 74.616 ;
     RECT  62.104 60.336 62.453 64.104 ;
     RECT  62.453 60.96 62.483 64.104 ;
     RECT  62.243 66.048 62.777 66.408 ;
     RECT  62.483 60.96 62.813 61.224 ;
     RECT  62.104 67.92 62.885 70.152 ;
     RECT  62.885 68.4 62.915 69.672 ;
     RECT  62.777 66.048 62.957 66.264 ;
     RECT  62.483 62.784 63.101 63.864 ;
     RECT  62.104 72.912 63.137 72.936 ;
     RECT  63.101 62.784 63.209 62.808 ;
     RECT  62.957 66.048 63.317 66.072 ;
     RECT  62.915 68.4 63.317 68.952 ;
     RECT  63.317 68.928 63.461 68.952 ;
     RECT  62.104 51.072 65.297 51.384 ;
     RECT  65.297 51.36 65.545 51.384 ;
     RECT  65.545 51.36 65.585 51.672 ;
     RECT  62.104 36.912 67.208 36.936 ;
     RECT  65.585 51.648 67.208 51.672 ;
     RECT  67.208 2.148 67.312 84.252 ;
     RECT  67.312 2.418 67.504 83.982 ;
     RECT  67.504 36.912 72.608 36.936 ;
     RECT  67.504 51.648 72.608 51.672 ;
     RECT  72.608 2.148 72.712 84.252 ;
     RECT  72.712 2.418 72.904 83.982 ;
     RECT  72.904 36.912 78.008 36.936 ;
     RECT  72.904 51.648 78.008 51.672 ;
     RECT  78.008 2.148 78.112 84.252 ;
     RECT  78.112 2.418 78.304 83.982 ;
     RECT  78.304 51.648 80.633 51.672 ;
     RECT  78.304 36.912 82.109 36.936 ;
     RECT  83.408 2.148 83.512 84.252 ;
     RECT  83.512 2.418 83.704 83.982 ;
     RECT  84.805 34.608 84.841 34.632 ;
     RECT  84.841 34.224 84.877 34.632 ;
     RECT  83.704 52.272 84.877 52.776 ;
     RECT  84.841 53.904 84.877 53.928 ;
     RECT  84.877 34.032 84.913 34.632 ;
     RECT  84.913 33.456 84.949 34.632 ;
     RECT  84.877 52.272 85.417 53.928 ;
     RECT  84.949 33.36 85.489 34.632 ;
     RECT  85.417 52.272 85.489 54.024 ;
     RECT  85.489 51.408 86.065 54.024 ;
     RECT  86.065 51.408 86.137 54.216 ;
     RECT  85.489 32.784 86.245 34.632 ;
     RECT  86.245 32.688 86.281 34.632 ;
     RECT  86.281 32.592 86.364 34.632 ;
     RECT  86.137 51.408 86.364 54.408 ;
    LAYER M5 ;
     RECT  44.112 0.016 44.232 1.763 ;
     RECT  2.4 2.137 2.52 2.151 ;
     RECT  7.8 2.137 7.92 2.151 ;
     RECT  13.2 2.137 13.32 2.151 ;
     RECT  18.6 2.137 18.72 2.151 ;
     RECT  24 2.137 24.12 2.151 ;
     RECT  29.4 2.137 29.52 2.151 ;
     RECT  34.8 2.137 34.92 2.151 ;
     RECT  40.2 2.137 40.32 2.151 ;
     RECT  45.6 2.137 45.72 2.151 ;
     RECT  51 2.137 51.12 2.151 ;
     RECT  56.4 2.137 56.52 2.151 ;
     RECT  61.8 2.137 61.92 2.151 ;
     RECT  67.2 2.137 67.32 2.151 ;
     RECT  72.6 2.137 72.72 2.151 ;
     RECT  78 2.137 78.12 2.151 ;
     RECT  83.4 2.137 83.52 2.151 ;
     RECT  45.6 2.151 45.912 3.685 ;
     RECT  43.344 45.541 43.368 46.211 ;
     RECT  40.2 2.151 40.512 46.309 ;
     RECT  36.864 46.117 36.888 46.787 ;
     RECT  45.6 3.685 46.824 46.885 ;
     RECT  44.928 46.885 46.824 47.315 ;
     RECT  39.312 46.309 40.512 48.661 ;
     RECT  39.024 48.661 40.512 48.707 ;
     RECT  51 2.151 51.312 48.853 ;
     RECT  49.152 46.789 49.176 48.949 ;
     RECT  56.4 2.151 56.712 48.949 ;
     RECT  49.008 48.949 49.176 48.995 ;
     RECT  39.024 48.707 39.048 49.043 ;
     RECT  49.008 48.995 49.032 49.091 ;
     RECT  44.928 47.315 46.728 49.187 ;
     RECT  36.816 47.269 36.84 49.477 ;
     RECT  40.2 48.707 40.512 49.525 ;
     RECT  36.816 49.477 37.608 50.053 ;
     RECT  36.432 50.053 37.608 50.099 ;
     RECT  36.432 50.099 36.84 50.387 ;
     RECT  45.6 49.187 46.728 50.629 ;
     RECT  40.2 49.525 40.632 50.677 ;
     RECT  50.496 48.853 51.312 50.677 ;
     RECT  45.6 50.629 47.592 50.723 ;
     RECT  54.768 50.725 54.792 50.867 ;
     RECT  45.6 50.723 46.248 50.917 ;
     RECT  50.496 50.677 51.912 51.011 ;
     RECT  55.872 48.949 56.712 51.157 ;
     RECT  36.432 50.387 36.456 51.347 ;
     RECT  50.688 51.011 51.912 51.683 ;
     RECT  53.04 51.253 53.064 51.923 ;
     RECT  55.584 51.157 56.712 51.925 ;
     RECT  50.688 51.683 51.312 52.067 ;
     RECT  40.2 50.677 41.304 52.211 ;
     RECT  45.504 50.917 46.248 52.309 ;
     RECT  47.568 50.723 47.592 52.309 ;
     RECT  45.504 52.309 47.592 52.355 ;
     RECT  31.104 50.245 31.128 52.405 ;
     RECT  54.672 51.925 56.712 52.451 ;
     RECT  55.584 52.451 56.712 52.499 ;
     RECT  29.4 2.151 29.712 52.981 ;
     RECT  31.104 52.405 31.896 52.981 ;
     RECT  56.4 52.499 56.712 52.981 ;
     RECT  29.4 52.981 31.896 53.027 ;
     RECT  38.832 51.781 38.856 53.027 ;
     RECT  45.504 52.355 47.064 53.075 ;
     RECT  59.52 47.845 59.544 53.075 ;
     RECT  36.24 52.309 36.264 53.171 ;
     RECT  31.872 53.027 31.896 53.555 ;
     RECT  45.6 53.075 47.064 53.555 ;
     RECT  56.4 52.981 56.808 53.555 ;
     RECT  29.4 53.027 30.504 53.795 ;
     RECT  36.48 53.509 36.504 53.797 ;
     RECT  53.856 52.981 53.88 53.845 ;
     RECT  40.2 52.211 40.632 54.085 ;
     RECT  53.424 53.845 53.88 54.133 ;
     RECT  48.672 50.677 48.696 54.467 ;
     RECT  34.8 2.151 35.112 54.469 ;
     RECT  55.248 53.941 55.272 54.515 ;
     RECT  45.6 53.555 46.776 54.563 ;
     RECT  45.6 54.563 46.248 54.661 ;
     RECT  43.776 54.373 43.8 54.755 ;
     RECT  53.424 54.133 54.216 55.237 ;
     RECT  51 52.067 51.312 55.765 ;
     RECT  53.424 55.237 54.744 55.909 ;
     RECT  39.36 54.085 40.632 55.955 ;
     RECT  53.424 55.909 55.224 55.955 ;
     RECT  29.4 53.795 29.712 56.341 ;
     RECT  33.984 54.469 35.112 56.341 ;
     RECT  36.48 53.797 36.888 56.387 ;
     RECT  36.48 56.387 36.84 56.531 ;
     RECT  45.36 54.661 46.248 56.533 ;
     RECT  56.4 53.555 56.712 56.533 ;
     RECT  55.2 55.955 55.224 56.771 ;
     RECT  45.168 56.533 46.248 56.963 ;
     RECT  40.2 55.955 40.632 56.965 ;
     RECT  31.872 55.813 31.896 57.013 ;
     RECT  39.888 56.965 40.632 57.013 ;
     RECT  28.464 56.341 29.712 57.059 ;
     RECT  31.104 57.013 31.896 57.059 ;
     RECT  56.4 56.533 56.904 57.395 ;
     RECT  27.408 56.965 27.432 57.589 ;
     RECT  27.408 57.589 27.768 57.635 ;
     RECT  33.984 56.341 35.208 57.635 ;
     RECT  53.424 55.955 54.216 58.069 ;
     RECT  39.888 57.013 41.352 58.163 ;
     RECT  45.408 56.963 46.248 58.163 ;
     RECT  48.48 56.245 48.504 58.163 ;
     RECT  36.72 56.531 36.84 58.355 ;
     RECT  27.744 57.635 27.768 58.643 ;
     RECT  45.6 58.163 46.248 58.645 ;
     RECT  51 55.765 52.152 58.691 ;
     RECT  59.856 56.965 59.88 58.691 ;
     RECT  33.984 57.635 35.112 58.693 ;
     RECT  53.424 58.069 54.408 58.693 ;
     RECT  36.816 58.355 36.84 59.027 ;
     RECT  61.8 2.151 62.112 59.029 ;
     RECT  40.2 58.163 41.352 59.077 ;
     RECT  42.72 56.437 42.744 59.077 ;
     RECT  31.104 57.059 31.128 59.171 ;
     RECT  40.2 59.077 42.744 59.219 ;
     RECT  56.4 57.395 56.856 59.219 ;
     RECT  24 2.151 24.312 59.221 ;
     RECT  26.064 58.117 26.088 59.221 ;
     RECT  29.4 57.059 29.712 59.221 ;
     RECT  24 59.221 26.088 59.315 ;
     RECT  33.84 58.693 35.112 59.459 ;
     RECT  45.6 58.645 46.68 59.507 ;
     RECT  38.208 56.581 38.232 59.845 ;
     RECT  38.208 59.845 38.568 59.891 ;
     RECT  42.288 59.219 42.744 59.891 ;
     RECT  53.424 58.693 54.696 59.891 ;
     RECT  0.192 28.069 0.216 60.131 ;
     RECT  53.424 59.891 53.448 60.229 ;
     RECT  54.672 59.891 54.696 60.275 ;
     RECT  40.2 59.219 41.064 60.323 ;
     RECT  29.04 59.221 29.712 60.373 ;
     RECT  45.6 59.507 46.392 60.373 ;
     RECT  53.136 60.229 53.448 60.419 ;
     RECT  24 59.315 25.656 60.467 ;
     RECT  29.04 60.373 30.168 60.515 ;
     RECT  51 58.691 51.312 60.805 ;
     RECT  42.72 59.891 42.744 60.949 ;
     RECT  60.96 59.029 62.112 60.949 ;
     RECT  60.96 60.949 62.472 61.043 ;
     RECT  34.704 59.459 35.112 61.141 ;
     RECT  44.688 60.373 46.392 61.475 ;
     RECT  25.632 60.467 25.656 61.619 ;
     RECT  27.12 60.949 27.144 61.619 ;
     RECT  29.4 60.515 30.168 61.619 ;
     RECT  42.672 60.949 42.744 61.619 ;
     RECT  42.672 61.619 42.696 61.715 ;
     RECT  50.784 60.805 51.312 61.765 ;
     RECT  24 60.467 24.312 62.005 ;
     RECT  38.544 59.891 38.568 62.581 ;
     RECT  48.72 59.797 48.744 62.771 ;
     RECT  24 62.005 25.224 62.819 ;
     RECT  56.4 59.219 56.712 62.821 ;
     RECT  50.688 61.765 51.312 63.107 ;
     RECT  56.4 62.821 57 63.155 ;
     RECT  34.368 61.141 35.112 63.205 ;
     RECT  38.16 62.581 38.568 63.299 ;
     RECT  44.448 62.005 44.472 63.299 ;
     RECT  61.8 61.043 62.472 64.021 ;
     RECT  61.632 64.021 62.472 64.115 ;
     RECT  61.632 64.115 62.232 64.307 ;
     RECT  56.4 63.155 56.712 64.357 ;
     RECT  29.4 61.619 29.712 64.693 ;
     RECT  34.128 63.205 35.112 64.933 ;
     RECT  31.92 63.013 31.944 65.027 ;
     RECT  45.6 61.475 46.392 65.029 ;
     RECT  45.12 65.029 46.392 65.219 ;
     RECT  55.44 64.357 56.808 65.363 ;
     RECT  38.544 63.299 38.568 65.509 ;
     RECT  53.136 60.419 53.16 65.509 ;
     RECT  58.368 60.949 58.392 65.653 ;
     RECT  58.176 65.653 58.392 65.699 ;
     RECT  50.88 63.107 51.312 65.749 ;
     RECT  28.416 64.693 29.712 65.797 ;
     RECT  61.8 64.307 62.232 66.083 ;
     RECT  24 62.819 24.312 66.085 ;
     RECT  28.416 65.797 30.36 66.227 ;
     RECT  38.16 65.509 38.568 66.469 ;
     RECT  45.6 65.219 46.392 66.755 ;
     RECT  38.112 66.469 38.568 66.901 ;
     RECT  55.584 65.363 56.808 67.189 ;
     RECT  61.8 66.083 62.112 67.237 ;
     RECT  47.904 65.077 47.928 67.283 ;
     RECT  53.136 65.509 53.496 67.283 ;
     RECT  29.4 66.227 30.36 67.669 ;
     RECT  53.136 67.283 53.16 67.669 ;
     RECT  29.04 67.669 30.36 67.715 ;
     RECT  50.736 65.749 51.312 67.765 ;
     RECT  24 66.085 24.552 67.859 ;
     RECT  55.584 67.189 57 68.003 ;
     RECT  38.112 66.901 38.76 68.053 ;
     RECT  53.04 67.669 53.16 68.243 ;
     RECT  40.2 60.323 40.512 68.245 ;
     RECT  27.696 67.765 27.72 68.341 ;
     RECT  29.04 67.715 29.712 68.341 ;
     RECT  43.296 67.285 43.32 68.435 ;
     RECT  45.6 66.755 45.912 68.629 ;
     RECT  37.632 68.053 38.76 68.677 ;
     RECT  40.08 68.245 40.512 68.677 ;
     RECT  45.6 68.629 46.248 68.725 ;
     RECT  37.632 68.677 40.512 68.819 ;
     RECT  45.6 68.725 46.344 68.867 ;
     RECT  45.6 68.867 46.248 68.915 ;
     RECT  59.232 65.845 59.256 68.915 ;
     RECT  61.68 67.237 62.112 68.915 ;
     RECT  61.8 68.915 62.112 68.917 ;
     RECT  55.584 68.003 56.808 68.963 ;
     RECT  31.728 67.093 31.752 69.205 ;
     RECT  47.904 68.341 47.928 69.253 ;
     RECT  53.136 68.243 53.16 69.253 ;
     RECT  50.496 67.765 51.312 69.299 ;
     RECT  44.592 68.917 44.616 69.301 ;
     RECT  45.6 68.915 46.008 69.301 ;
     RECT  27.696 68.341 29.712 69.349 ;
     RECT  58.176 65.699 58.2 69.493 ;
     RECT  27.312 69.349 29.712 69.539 ;
     RECT  61.8 68.917 62.904 69.683 ;
     RECT  34.08 64.933 35.112 69.829 ;
     RECT  44.592 69.301 46.008 69.925 ;
     RECT  47.904 69.253 48.504 69.971 ;
     RECT  55.584 68.963 56.712 70.019 ;
     RECT  39.648 68.819 40.512 70.691 ;
     RECT  27.312 69.539 27.72 70.739 ;
     RECT  44.592 69.925 46.536 70.835 ;
     RECT  48.432 69.971 48.504 70.933 ;
     RECT  37.632 68.819 38.568 70.981 ;
     RECT  31.728 69.205 32.664 71.075 ;
     RECT  53.136 69.253 53.592 71.221 ;
     RECT  61.8 69.683 62.112 71.221 ;
     RECT  27.696 70.739 27.72 71.315 ;
     RECT  34.08 69.829 35.496 71.315 ;
     RECT  30.72 70.117 30.744 71.363 ;
     RECT  58.176 69.493 58.632 71.749 ;
     RECT  31.728 71.075 31.752 71.797 ;
     RECT  53.136 71.221 54.12 71.891 ;
     RECT  48.432 70.933 48.6 71.989 ;
     RECT  29.4 69.539 29.712 72.037 ;
     RECT  37.344 70.981 38.568 72.083 ;
     RECT  31.296 71.797 31.752 72.421 ;
     RECT  37.584 72.083 38.568 72.515 ;
     RECT  30.816 72.421 31.752 72.563 ;
     RECT  34.08 71.315 35.112 72.805 ;
     RECT  40.2 70.691 40.512 72.805 ;
     RECT  48.24 71.989 48.6 72.805 ;
     RECT  41.808 70.789 41.832 72.851 ;
     RECT  61.584 71.221 62.112 72.851 ;
     RECT  58.176 71.749 59.112 72.947 ;
     RECT  37.584 72.515 37.896 72.995 ;
     RECT  53.136 71.891 53.256 73.187 ;
     RECT  26.88 72.901 26.904 73.235 ;
     RECT  31.296 72.563 31.752 73.235 ;
     RECT  56.4 70.019 56.712 73.237 ;
     RECT  53.232 73.187 53.256 73.283 ;
     RECT  58.176 72.947 58.2 73.283 ;
     RECT  44.592 70.835 46.344 73.381 ;
     RECT  50.784 69.299 51.312 73.571 ;
     RECT  39.456 72.805 40.512 73.811 ;
     RECT  34.08 72.805 35.208 73.909 ;
     RECT  33.936 73.909 35.208 74.437 ;
     RECT  48.24 72.805 48.696 75.397 ;
     RECT  51 73.571 51.312 75.397 ;
     RECT  56.016 73.237 56.712 75.397 ;
     RECT  51 75.397 51.528 75.539 ;
     RECT  56.016 75.397 56.856 75.539 ;
     RECT  48.24 75.397 49.032 75.685 ;
     RECT  31.728 73.235 31.752 75.781 ;
     RECT  37.872 72.995 37.896 75.781 ;
     RECT  29.28 72.037 29.712 75.971 ;
     RECT  48.24 75.685 49.128 76.213 ;
     RECT  40.2 73.811 40.512 76.933 ;
     RECT  54.912 76.309 54.936 76.979 ;
     RECT  43.296 75.205 43.32 77.027 ;
     RECT  33.792 74.437 35.208 77.413 ;
     RECT  37.056 75.781 37.896 77.555 ;
     RECT  39.456 76.933 40.512 77.555 ;
     RECT  51 75.539 51.312 77.557 ;
     RECT  26.4 75.637 26.424 77.699 ;
     RECT  48.24 76.213 49.608 77.845 ;
     RECT  50.88 77.557 51.312 77.845 ;
     RECT  59.472 74.629 59.496 77.989 ;
     RECT  59.28 77.989 59.496 78.035 ;
     RECT  31.152 75.781 31.848 78.037 ;
     RECT  48.24 77.845 51.312 78.517 ;
     RECT  33.792 77.413 35.256 78.613 ;
     RECT  44.4 73.381 46.344 78.613 ;
     RECT  47.712 78.517 51.312 78.947 ;
     RECT  59.28 78.035 59.304 79.187 ;
     RECT  40.2 77.555 40.512 79.189 ;
     RECT  43.68 78.613 46.344 79.189 ;
     RECT  54.432 78.613 54.456 79.235 ;
     RECT  27.312 78.613 27.336 79.237 ;
     RECT  29.4 75.971 29.712 79.525 ;
     RECT  37.632 77.555 37.656 79.571 ;
     RECT  26.88 79.237 27.336 79.763 ;
     RECT  26.88 79.763 26.952 80.243 ;
     RECT  47.712 78.947 49.992 80.245 ;
     RECT  51 78.947 51.312 80.245 ;
     RECT  33.792 78.613 35.928 80.291 ;
     RECT  43.344 79.189 46.344 80.291 ;
     RECT  47.712 80.245 51.312 80.485 ;
     RECT  40.08 79.189 40.512 80.917 ;
     RECT  60.384 80.533 60.408 80.963 ;
     RECT  56.016 75.539 56.712 81.347 ;
     RECT  29.4 79.525 29.832 81.445 ;
     RECT  33.792 80.291 35.256 81.445 ;
     RECT  39.792 80.917 40.512 82.115 ;
     RECT  31.152 78.037 32.376 82.453 ;
     RECT  33.792 81.445 36.216 82.453 ;
     RECT  26.928 80.243 26.952 82.691 ;
     RECT  47.712 80.485 51.576 82.837 ;
     RECT  47.712 82.837 52.296 82.931 ;
     RECT  31.152 82.453 36.216 82.979 ;
     RECT  56.112 81.347 56.712 83.075 ;
     RECT  29.4 81.445 29.928 83.267 ;
     RECT  58.752 80.533 58.776 83.267 ;
     RECT  53.904 83.173 53.928 83.795 ;
     RECT  48.24 82.931 52.296 83.891 ;
     RECT  48.24 83.891 51.312 84.181 ;
     RECT  2.4 2.151 2.712 84.249 ;
     RECT  7.8 2.151 8.112 84.249 ;
     RECT  13.2 2.151 13.512 84.249 ;
     RECT  18.6 2.151 18.912 84.249 ;
     RECT  24 67.859 24.312 84.249 ;
     RECT  29.4 83.267 29.712 84.249 ;
     RECT  40.2 82.115 40.512 84.249 ;
     RECT  48.048 84.181 51.312 84.249 ;
     RECT  56.4 83.075 56.712 84.249 ;
     RECT  61.8 72.851 62.112 84.249 ;
     RECT  67.2 2.151 67.512 84.249 ;
     RECT  72.6 2.151 72.912 84.249 ;
     RECT  78 2.151 78.312 84.249 ;
     RECT  83.4 2.151 83.712 84.249 ;
     RECT  2.4 84.249 2.52 84.263 ;
     RECT  7.8 84.249 7.92 84.263 ;
     RECT  13.2 84.249 13.32 84.263 ;
     RECT  18.6 84.249 18.72 84.263 ;
     RECT  24 84.249 24.12 84.263 ;
     RECT  29.4 84.249 29.52 84.263 ;
     RECT  40.2 84.249 40.32 84.263 ;
     RECT  48.048 84.249 51.12 84.263 ;
     RECT  56.4 84.249 56.52 84.263 ;
     RECT  61.8 84.249 61.92 84.263 ;
     RECT  67.2 84.249 67.32 84.263 ;
     RECT  72.6 84.249 72.72 84.263 ;
     RECT  78 84.249 78.12 84.263 ;
     RECT  83.4 84.249 83.52 84.263 ;
     RECT  44.304 80.291 46.344 84.325 ;
     RECT  44.208 84.325 46.344 85.381 ;
     RECT  31.152 82.979 35.256 85.477 ;
     RECT  44.208 85.381 46.536 85.477 ;
     RECT  30.864 85.477 35.256 86.053 ;
     RECT  30.768 86.053 35.256 86.147 ;
     RECT  44.208 85.477 46.824 86.149 ;
     RECT  48.048 84.263 50.856 86.149 ;
     RECT  44.208 86.149 50.856 86.197 ;
     RECT  30.768 86.147 35.208 86.243 ;
     RECT  30.768 86.243 34.92 86.352 ;
     RECT  44.208 86.197 51.048 86.352 ;
     RECT  39.048 48.707 40.2 49.043 ;
     RECT  49.176 48.853 50.496 48.995 ;
     RECT  49.032 48.995 50.496 49.091 ;
     RECT  35.112 50.053 36.432 51.347 ;
     RECT  29.712 50.245 31.104 52.981 ;
     RECT  47.592 50.677 48.672 52.355 ;
     RECT  46.248 50.723 47.568 52.309 ;
     RECT  54.792 50.725 55.872 50.867 ;
     RECT  54.768 50.867 55.872 51.157 ;
     RECT  54.768 51.157 55.584 51.925 ;
     RECT  51.912 51.253 53.04 51.683 ;
     RECT  35.112 51.347 36.264 52.309 ;
     RECT  38.856 51.781 40.2 53.027 ;
     RECT  35.112 52.309 36.24 53.171 ;
     RECT  54.672 52.451 55.584 52.499 ;
     RECT  54.672 52.499 56.4 52.981 ;
     RECT  53.88 52.981 56.4 53.941 ;
     RECT  30.504 53.027 31.872 53.555 ;
     RECT  39.36 53.027 40.2 54.085 ;
     RECT  35.112 53.171 36.264 53.509 ;
     RECT  35.112 53.509 36.48 56.341 ;
     RECT  53.88 53.941 55.248 54.133 ;
     RECT  55.272 53.941 56.4 54.515 ;
     RECT  54.216 54.133 55.248 54.515 ;
     RECT  54.216 54.515 56.4 55.237 ;
     RECT  54.744 55.237 56.4 55.909 ;
     RECT  52.152 55.765 53.424 58.691 ;
     RECT  55.224 55.909 56.4 56.771 ;
     RECT  39.888 55.955 40.2 56.965 ;
     RECT  54.216 55.955 55.2 56.771 ;
     RECT  35.208 56.341 36.48 56.531 ;
     RECT  36.84 56.387 36.888 56.581 ;
     RECT  35.208 56.531 36.72 57.635 ;
     RECT  36.84 56.581 38.208 59.027 ;
     RECT  54.216 56.771 54.408 58.069 ;
     RECT  27.432 56.965 28.464 57.059 ;
     RECT  29.712 57.013 31.104 59.171 ;
     RECT  41.352 57.013 42.72 59.077 ;
     RECT  27.432 57.059 27.768 57.589 ;
     RECT  29.712 59.171 30.168 60.373 ;
     RECT  41.064 59.219 42.288 59.891 ;
     RECT  42.672 59.891 42.72 60.949 ;
     RECT  53.448 59.891 54.672 60.275 ;
     RECT  24.312 60.467 25.632 61.619 ;
     RECT  25.656 60.949 27.12 61.619 ;
     RECT  44.688 61.475 45.6 62.005 ;
     RECT  24.312 61.619 25.224 62.005 ;
     RECT  44.472 62.005 45.6 63.299 ;
     RECT  57 62.821 58.368 63.155 ;
     RECT  56.712 63.155 56.808 64.357 ;
     RECT  46.392 65.077 47.904 66.755 ;
     RECT  56.808 65.653 58.176 67.189 ;
     RECT  58.2 65.699 58.392 65.845 ;
     RECT  58.2 65.845 59.232 68.915 ;
     RECT  29.04 66.227 29.4 67.669 ;
     RECT  38.76 66.901 40.2 68.245 ;
     RECT  30.36 67.093 31.728 67.715 ;
     RECT  57 67.189 58.176 68.003 ;
     RECT  47.904 67.283 47.928 68.341 ;
     RECT  27.72 67.765 29.04 68.341 ;
     RECT  56.808 68.003 58.176 68.963 ;
     RECT  38.76 68.245 40.08 68.677 ;
     RECT  38.568 68.819 39.648 70.691 ;
     RECT  46.248 68.867 46.344 68.915 ;
     RECT  46.008 68.915 46.344 69.925 ;
     RECT  58.2 68.915 58.632 69.493 ;
     RECT  44.616 68.917 45.6 69.301 ;
     RECT  56.712 68.963 58.176 73.283 ;
     RECT  32.664 69.205 34.08 71.075 ;
     RECT  46.536 69.925 47.904 69.971 ;
     RECT  29.712 70.117 30.72 71.363 ;
     RECT  30.744 70.117 31.728 71.363 ;
     RECT  40.512 70.789 41.808 72.851 ;
     RECT  35.112 71.315 35.208 72.805 ;
     RECT  29.712 71.363 31.728 71.797 ;
     RECT  29.712 71.797 31.296 72.421 ;
     RECT  29.712 72.421 30.816 72.563 ;
     RECT  43.32 75.205 44.4 77.027 ;
     RECT  29.712 75.781 31.152 79.525 ;
     RECT  49.608 76.213 51 77.557 ;
     RECT  54.936 76.309 56.016 76.979 ;
     RECT  49.608 77.557 50.88 77.845 ;
     RECT  32.376 78.037 33.792 82.453 ;
     RECT  46.344 78.517 47.712 82.931 ;
     RECT  49.992 78.947 51 80.245 ;
     RECT  29.832 79.525 31.152 81.445 ;
     RECT  35.256 80.291 35.928 81.445 ;
     RECT  60.408 80.533 61.8 80.963 ;
     RECT  29.928 81.445 31.152 83.267 ;
     RECT  48.048 82.931 48.24 84.181 ;
     RECT  29.712 83.267 31.152 84.249 ;
     RECT  29.52 84.249 31.152 84.263 ;
     RECT  30.864 84.263 31.152 85.477 ;
     RECT  46.536 85.381 48.048 85.477 ;
     RECT  46.824 85.477 48.048 86.149 ;
  END
END ot_hgi_sm_pub_smrg_l3
END LIBRARY
